VERSION 5.7 ;
  NOWIREEXTENSIONATPIN ON ;
  DIVIDERCHAR "/" ;
  BUSBITCHARS "[]" ;
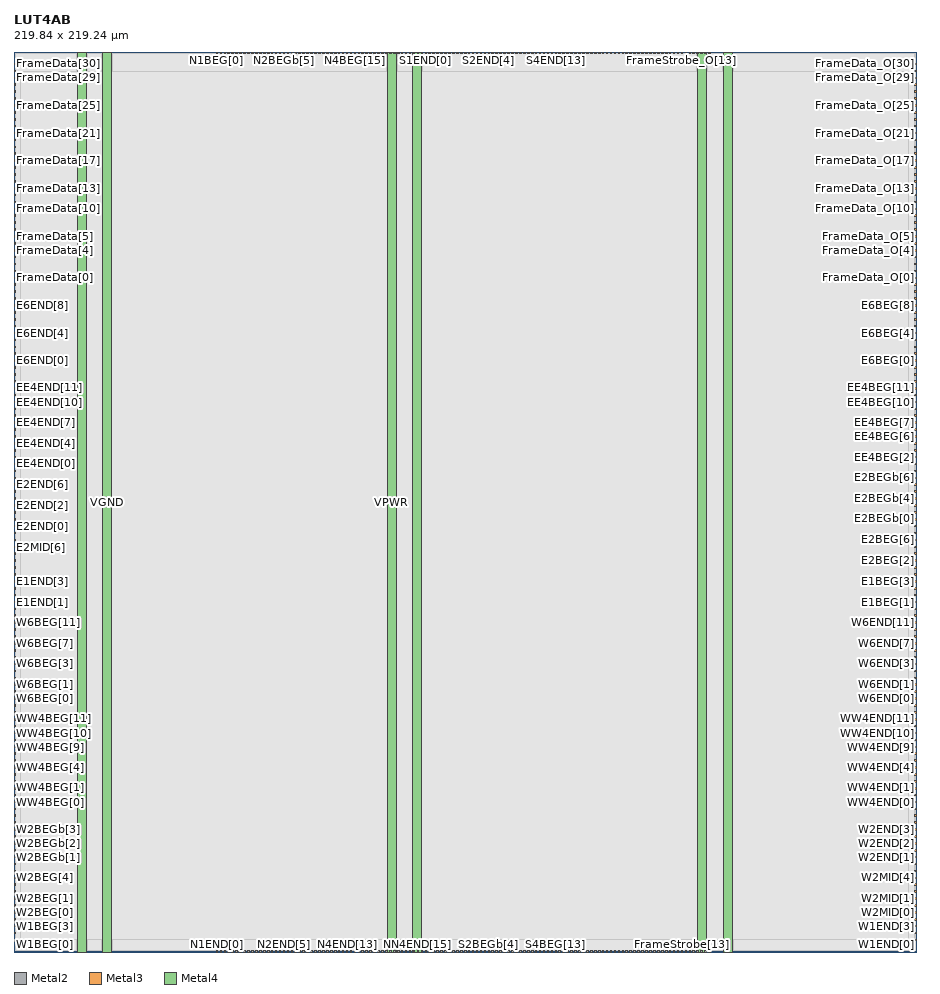
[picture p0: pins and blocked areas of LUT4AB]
MACRO LUT4AB
  CLASS BLOCK ;
  FOREIGN LUT4AB ;
  ORIGIN 0.000 0.000 ;
  SIZE 219.840 BY 219.240 ;
  PIN Ci
    DIRECTION INPUT ;
    USE SIGNAL ;
    ANTENNAGATEAREA 0.587600 ;
    PORT
      LAYER Metal2 ;
        RECT 99.160 0.000 99.560 0.400 ;
    END
  END Ci
  PIN Co
    DIRECTION OUTPUT ;
    USE SIGNAL ;
    ANTENNADIFFAREA 0.677200 ;
    PORT
      LAYER Metal2 ;
        RECT 99.160 218.840 99.560 219.240 ;
    END
  END Co
  PIN E1BEG[0]
    DIRECTION OUTPUT ;
    USE SIGNAL ;
    ANTENNADIFFAREA 0.708600 ;
    PORT
      LAYER Metal3 ;
        RECT 219.440 83.380 219.840 83.780 ;
    END
  END E1BEG[0]
  PIN E1BEG[1]
    DIRECTION OUTPUT ;
    USE SIGNAL ;
    ANTENNADIFFAREA 0.708600 ;
    PORT
      LAYER Metal3 ;
        RECT 219.440 85.060 219.840 85.460 ;
    END
  END E1BEG[1]
  PIN E1BEG[2]
    DIRECTION OUTPUT ;
    USE SIGNAL ;
    ANTENNADIFFAREA 0.708600 ;
    PORT
      LAYER Metal3 ;
        RECT 219.440 86.740 219.840 87.140 ;
    END
  END E1BEG[2]
  PIN E1BEG[3]
    DIRECTION OUTPUT ;
    USE SIGNAL ;
    ANTENNADIFFAREA 0.708600 ;
    PORT
      LAYER Metal3 ;
        RECT 219.440 88.420 219.840 88.820 ;
    END
  END E1BEG[3]
  PIN E1END[0]
    DIRECTION INPUT ;
    USE SIGNAL ;
    ANTENNAGATEAREA 1.917500 ;
    PORT
      LAYER Metal3 ;
        RECT 0.000 83.380 0.400 83.780 ;
    END
  END E1END[0]
  PIN E1END[1]
    DIRECTION INPUT ;
    USE SIGNAL ;
    ANTENNAGATEAREA 1.847300 ;
    PORT
      LAYER Metal3 ;
        RECT 0.000 85.060 0.400 85.460 ;
    END
  END E1END[1]
  PIN E1END[2]
    DIRECTION INPUT ;
    USE SIGNAL ;
    ANTENNAGATEAREA 2.448700 ;
    PORT
      LAYER Metal3 ;
        RECT 0.000 86.740 0.400 87.140 ;
    END
  END E1END[2]
  PIN E1END[3]
    DIRECTION INPUT ;
    USE SIGNAL ;
    ANTENNAGATEAREA 2.433100 ;
    PORT
      LAYER Metal3 ;
        RECT 0.000 88.420 0.400 88.820 ;
    END
  END E1END[3]
  PIN E2BEG[0]
    DIRECTION OUTPUT ;
    USE SIGNAL ;
    ANTENNADIFFAREA 0.708600 ;
    PORT
      LAYER Metal3 ;
        RECT 219.440 90.100 219.840 90.500 ;
    END
  END E2BEG[0]
  PIN E2BEG[1]
    DIRECTION OUTPUT ;
    USE SIGNAL ;
    ANTENNADIFFAREA 0.708600 ;
    PORT
      LAYER Metal3 ;
        RECT 219.440 91.780 219.840 92.180 ;
    END
  END E2BEG[1]
  PIN E2BEG[2]
    DIRECTION OUTPUT ;
    USE SIGNAL ;
    ANTENNADIFFAREA 0.708600 ;
    PORT
      LAYER Metal3 ;
        RECT 219.440 93.460 219.840 93.860 ;
    END
  END E2BEG[2]
  PIN E2BEG[3]
    DIRECTION OUTPUT ;
    USE SIGNAL ;
    ANTENNADIFFAREA 0.708600 ;
    PORT
      LAYER Metal3 ;
        RECT 219.440 95.140 219.840 95.540 ;
    END
  END E2BEG[3]
  PIN E2BEG[4]
    DIRECTION OUTPUT ;
    USE SIGNAL ;
    ANTENNADIFFAREA 0.708600 ;
    PORT
      LAYER Metal3 ;
        RECT 219.440 96.820 219.840 97.220 ;
    END
  END E2BEG[4]
  PIN E2BEG[5]
    DIRECTION OUTPUT ;
    USE SIGNAL ;
    ANTENNADIFFAREA 0.708600 ;
    PORT
      LAYER Metal3 ;
        RECT 219.440 98.500 219.840 98.900 ;
    END
  END E2BEG[5]
  PIN E2BEG[6]
    DIRECTION OUTPUT ;
    USE SIGNAL ;
    ANTENNADIFFAREA 0.708600 ;
    PORT
      LAYER Metal3 ;
        RECT 219.440 100.180 219.840 100.580 ;
    END
  END E2BEG[6]
  PIN E2BEG[7]
    DIRECTION OUTPUT ;
    USE SIGNAL ;
    ANTENNADIFFAREA 0.708600 ;
    PORT
      LAYER Metal3 ;
        RECT 219.440 101.860 219.840 102.260 ;
    END
  END E2BEG[7]
  PIN E2BEGb[0]
    DIRECTION OUTPUT ;
    USE SIGNAL ;
    ANTENNADIFFAREA 0.708600 ;
    PORT
      LAYER Metal3 ;
        RECT 219.440 103.540 219.840 103.940 ;
    END
  END E2BEGb[0]
  PIN E2BEGb[1]
    DIRECTION OUTPUT ;
    USE SIGNAL ;
    ANTENNADIFFAREA 0.708600 ;
    PORT
      LAYER Metal3 ;
        RECT 219.440 105.220 219.840 105.620 ;
    END
  END E2BEGb[1]
  PIN E2BEGb[2]
    DIRECTION OUTPUT ;
    USE SIGNAL ;
    ANTENNADIFFAREA 0.708600 ;
    PORT
      LAYER Metal3 ;
        RECT 219.440 106.900 219.840 107.300 ;
    END
  END E2BEGb[2]
  PIN E2BEGb[3]
    DIRECTION OUTPUT ;
    USE SIGNAL ;
    ANTENNADIFFAREA 0.708600 ;
    PORT
      LAYER Metal3 ;
        RECT 219.440 108.580 219.840 108.980 ;
    END
  END E2BEGb[3]
  PIN E2BEGb[4]
    DIRECTION OUTPUT ;
    USE SIGNAL ;
    ANTENNADIFFAREA 0.708600 ;
    PORT
      LAYER Metal3 ;
        RECT 219.440 110.260 219.840 110.660 ;
    END
  END E2BEGb[4]
  PIN E2BEGb[5]
    DIRECTION OUTPUT ;
    USE SIGNAL ;
    ANTENNADIFFAREA 0.708600 ;
    PORT
      LAYER Metal3 ;
        RECT 219.440 111.940 219.840 112.340 ;
    END
  END E2BEGb[5]
  PIN E2BEGb[6]
    DIRECTION OUTPUT ;
    USE SIGNAL ;
    ANTENNADIFFAREA 0.708600 ;
    PORT
      LAYER Metal3 ;
        RECT 219.440 113.620 219.840 114.020 ;
    END
  END E2BEGb[6]
  PIN E2BEGb[7]
    DIRECTION OUTPUT ;
    USE SIGNAL ;
    ANTENNADIFFAREA 0.708600 ;
    PORT
      LAYER Metal3 ;
        RECT 219.440 115.300 219.840 115.700 ;
    END
  END E2BEGb[7]
  PIN E2END[0]
    DIRECTION INPUT ;
    USE SIGNAL ;
    ANTENNAGATEAREA 0.944600 ;
    PORT
      LAYER Metal3 ;
        RECT 0.000 103.540 0.400 103.940 ;
    END
  END E2END[0]
  PIN E2END[1]
    DIRECTION INPUT ;
    USE SIGNAL ;
    ANTENNAGATEAREA 0.899100 ;
    PORT
      LAYER Metal3 ;
        RECT 0.000 105.220 0.400 105.620 ;
    END
  END E2END[1]
  PIN E2END[2]
    DIRECTION INPUT ;
    USE SIGNAL ;
    ANTENNAGATEAREA 1.498900 ;
    PORT
      LAYER Metal3 ;
        RECT 0.000 106.900 0.400 107.300 ;
    END
  END E2END[2]
  PIN E2END[3]
    DIRECTION INPUT ;
    USE SIGNAL ;
    ANTENNAGATEAREA 1.530100 ;
    PORT
      LAYER Metal3 ;
        RECT 0.000 108.580 0.400 108.980 ;
    END
  END E2END[3]
  PIN E2END[4]
    DIRECTION INPUT ;
    USE SIGNAL ;
    ANTENNAGATEAREA 1.059500 ;
    PORT
      LAYER Metal3 ;
        RECT 0.000 110.260 0.400 110.660 ;
    END
  END E2END[4]
  PIN E2END[5]
    DIRECTION INPUT ;
    USE SIGNAL ;
    ANTENNAGATEAREA 1.288300 ;
    PORT
      LAYER Metal3 ;
        RECT 0.000 111.940 0.400 112.340 ;
    END
  END E2END[5]
  PIN E2END[6]
    DIRECTION INPUT ;
    USE SIGNAL ;
    ANTENNAGATEAREA 1.439400 ;
    PORT
      LAYER Metal3 ;
        RECT 0.000 113.620 0.400 114.020 ;
    END
  END E2END[6]
  PIN E2END[7]
    DIRECTION INPUT ;
    USE SIGNAL ;
    ANTENNAGATEAREA 1.041300 ;
    PORT
      LAYER Metal3 ;
        RECT 0.000 115.300 0.400 115.700 ;
    END
  END E2END[7]
  PIN E2MID[0]
    DIRECTION INPUT ;
    USE SIGNAL ;
    ANTENNAGATEAREA 0.820300 ;
    ANTENNADIFFAREA 32.246399 ;
    PORT
      LAYER Metal3 ;
        RECT 0.000 90.100 0.400 90.500 ;
    END
  END E2MID[0]
  PIN E2MID[1]
    DIRECTION INPUT ;
    USE SIGNAL ;
    ANTENNAGATEAREA 1.033500 ;
    ANTENNADIFFAREA 10.077000 ;
    PORT
      LAYER Metal3 ;
        RECT 0.000 91.780 0.400 92.180 ;
    END
  END E2MID[1]
  PIN E2MID[2]
    DIRECTION INPUT ;
    USE SIGNAL ;
    ANTENNAGATEAREA 0.848900 ;
    ANTENNADIFFAREA 24.184799 ;
    PORT
      LAYER Metal3 ;
        RECT 0.000 93.460 0.400 93.860 ;
    END
  END E2MID[2]
  PIN E2MID[3]
    DIRECTION INPUT ;
    USE SIGNAL ;
    ANTENNAGATEAREA 1.033500 ;
    ANTENNADIFFAREA 50.384998 ;
    PORT
      LAYER Metal3 ;
        RECT 0.000 95.140 0.400 95.540 ;
    END
  END E2MID[3]
  PIN E2MID[4]
    DIRECTION INPUT ;
    USE SIGNAL ;
    ANTENNAGATEAREA 0.820300 ;
    ANTENNADIFFAREA 32.246399 ;
    PORT
      LAYER Metal3 ;
        RECT 0.000 96.820 0.400 97.220 ;
    END
  END E2MID[4]
  PIN E2MID[5]
    DIRECTION INPUT ;
    USE SIGNAL ;
    ANTENNAGATEAREA 1.033500 ;
    PORT
      LAYER Metal3 ;
        RECT 0.000 98.500 0.400 98.900 ;
    END
  END E2MID[5]
  PIN E2MID[6]
    DIRECTION INPUT ;
    USE SIGNAL ;
    ANTENNAGATEAREA 0.820300 ;
    PORT
      LAYER Metal3 ;
        RECT 0.000 100.180 0.400 100.580 ;
    END
  END E2MID[6]
  PIN E2MID[7]
    DIRECTION INPUT ;
    USE SIGNAL ;
    ANTENNAGATEAREA 1.033500 ;
    PORT
      LAYER Metal3 ;
        RECT 0.000 101.860 0.400 102.260 ;
    END
  END E2MID[7]
  PIN E6BEG[0]
    DIRECTION OUTPUT ;
    USE SIGNAL ;
    ANTENNADIFFAREA 0.708600 ;
    PORT
      LAYER Metal3 ;
        RECT 219.440 143.860 219.840 144.260 ;
    END
  END E6BEG[0]
  PIN E6BEG[10]
    DIRECTION OUTPUT ;
    USE SIGNAL ;
    ANTENNADIFFAREA 0.708600 ;
    PORT
      LAYER Metal3 ;
        RECT 219.440 160.660 219.840 161.060 ;
    END
  END E6BEG[10]
  PIN E6BEG[11]
    DIRECTION OUTPUT ;
    USE SIGNAL ;
    ANTENNADIFFAREA 0.708600 ;
    PORT
      LAYER Metal3 ;
        RECT 219.440 162.340 219.840 162.740 ;
    END
  END E6BEG[11]
  PIN E6BEG[1]
    DIRECTION OUTPUT ;
    USE SIGNAL ;
    ANTENNADIFFAREA 0.708600 ;
    PORT
      LAYER Metal3 ;
        RECT 219.440 145.540 219.840 145.940 ;
    END
  END E6BEG[1]
  PIN E6BEG[2]
    DIRECTION OUTPUT ;
    USE SIGNAL ;
    ANTENNADIFFAREA 0.708600 ;
    PORT
      LAYER Metal3 ;
        RECT 219.440 147.220 219.840 147.620 ;
    END
  END E6BEG[2]
  PIN E6BEG[3]
    DIRECTION OUTPUT ;
    USE SIGNAL ;
    ANTENNADIFFAREA 0.708600 ;
    PORT
      LAYER Metal3 ;
        RECT 219.440 148.900 219.840 149.300 ;
    END
  END E6BEG[3]
  PIN E6BEG[4]
    DIRECTION OUTPUT ;
    USE SIGNAL ;
    ANTENNADIFFAREA 0.708600 ;
    PORT
      LAYER Metal3 ;
        RECT 219.440 150.580 219.840 150.980 ;
    END
  END E6BEG[4]
  PIN E6BEG[5]
    DIRECTION OUTPUT ;
    USE SIGNAL ;
    ANTENNADIFFAREA 0.708600 ;
    PORT
      LAYER Metal3 ;
        RECT 219.440 152.260 219.840 152.660 ;
    END
  END E6BEG[5]
  PIN E6BEG[6]
    DIRECTION OUTPUT ;
    USE SIGNAL ;
    ANTENNADIFFAREA 0.708600 ;
    PORT
      LAYER Metal3 ;
        RECT 219.440 153.940 219.840 154.340 ;
    END
  END E6BEG[6]
  PIN E6BEG[7]
    DIRECTION OUTPUT ;
    USE SIGNAL ;
    ANTENNADIFFAREA 0.708600 ;
    PORT
      LAYER Metal3 ;
        RECT 219.440 155.620 219.840 156.020 ;
    END
  END E6BEG[7]
  PIN E6BEG[8]
    DIRECTION OUTPUT ;
    USE SIGNAL ;
    ANTENNADIFFAREA 0.708600 ;
    PORT
      LAYER Metal3 ;
        RECT 219.440 157.300 219.840 157.700 ;
    END
  END E6BEG[8]
  PIN E6BEG[9]
    DIRECTION OUTPUT ;
    USE SIGNAL ;
    ANTENNADIFFAREA 0.708600 ;
    PORT
      LAYER Metal3 ;
        RECT 219.440 158.980 219.840 159.380 ;
    END
  END E6BEG[9]
  PIN E6END[0]
    DIRECTION INPUT ;
    USE SIGNAL ;
    ANTENNAGATEAREA 2.678800 ;
    PORT
      LAYER Metal3 ;
        RECT 0.000 143.860 0.400 144.260 ;
    END
  END E6END[0]
  PIN E6END[10]
    DIRECTION INPUT ;
    USE SIGNAL ;
    ANTENNAGATEAREA 0.180700 ;
    PORT
      LAYER Metal3 ;
        RECT 0.000 160.660 0.400 161.060 ;
    END
  END E6END[10]
  PIN E6END[11]
    DIRECTION INPUT ;
    USE SIGNAL ;
    ANTENNAGATEAREA 0.180700 ;
    PORT
      LAYER Metal3 ;
        RECT 0.000 162.340 0.400 162.740 ;
    END
  END E6END[11]
  PIN E6END[1]
    DIRECTION INPUT ;
    USE SIGNAL ;
    ANTENNAGATEAREA 2.637700 ;
    PORT
      LAYER Metal3 ;
        RECT 0.000 145.540 0.400 145.940 ;
    END
  END E6END[1]
  PIN E6END[2]
    DIRECTION INPUT ;
    USE SIGNAL ;
    ANTENNAGATEAREA 0.180700 ;
    ANTENNADIFFAREA 2.015400 ;
    PORT
      LAYER Metal3 ;
        RECT 0.000 147.220 0.400 147.620 ;
    END
  END E6END[2]
  PIN E6END[3]
    DIRECTION INPUT ;
    USE SIGNAL ;
    ANTENNAGATEAREA 0.180700 ;
    ANTENNADIFFAREA 2.015400 ;
    PORT
      LAYER Metal3 ;
        RECT 0.000 148.900 0.400 149.300 ;
    END
  END E6END[3]
  PIN E6END[4]
    DIRECTION INPUT ;
    USE SIGNAL ;
    ANTENNAGATEAREA 0.180700 ;
    PORT
      LAYER Metal3 ;
        RECT 0.000 150.580 0.400 150.980 ;
    END
  END E6END[4]
  PIN E6END[5]
    DIRECTION INPUT ;
    USE SIGNAL ;
    ANTENNAGATEAREA 0.180700 ;
    ANTENNADIFFAREA 2.015400 ;
    PORT
      LAYER Metal3 ;
        RECT 0.000 152.260 0.400 152.660 ;
    END
  END E6END[5]
  PIN E6END[6]
    DIRECTION INPUT ;
    USE SIGNAL ;
    ANTENNAGATEAREA 0.180700 ;
    PORT
      LAYER Metal3 ;
        RECT 0.000 153.940 0.400 154.340 ;
    END
  END E6END[6]
  PIN E6END[7]
    DIRECTION INPUT ;
    USE SIGNAL ;
    ANTENNAGATEAREA 0.180700 ;
    PORT
      LAYER Metal3 ;
        RECT 0.000 155.620 0.400 156.020 ;
    END
  END E6END[7]
  PIN E6END[8]
    DIRECTION INPUT ;
    USE SIGNAL ;
    ANTENNAGATEAREA 0.180700 ;
    PORT
      LAYER Metal3 ;
        RECT 0.000 157.300 0.400 157.700 ;
    END
  END E6END[8]
  PIN E6END[9]
    DIRECTION INPUT ;
    USE SIGNAL ;
    ANTENNAGATEAREA 0.180700 ;
    PORT
      LAYER Metal3 ;
        RECT 0.000 158.980 0.400 159.380 ;
    END
  END E6END[9]
  PIN EE4BEG[0]
    DIRECTION OUTPUT ;
    USE SIGNAL ;
    ANTENNADIFFAREA 0.708600 ;
    PORT
      LAYER Metal3 ;
        RECT 219.440 116.980 219.840 117.380 ;
    END
  END EE4BEG[0]
  PIN EE4BEG[10]
    DIRECTION OUTPUT ;
    USE SIGNAL ;
    ANTENNADIFFAREA 0.708600 ;
    PORT
      LAYER Metal3 ;
        RECT 219.440 133.780 219.840 134.180 ;
    END
  END EE4BEG[10]
  PIN EE4BEG[11]
    DIRECTION OUTPUT ;
    USE SIGNAL ;
    ANTENNADIFFAREA 0.708600 ;
    PORT
      LAYER Metal3 ;
        RECT 219.440 135.460 219.840 135.860 ;
    END
  END EE4BEG[11]
  PIN EE4BEG[12]
    DIRECTION OUTPUT ;
    USE SIGNAL ;
    ANTENNADIFFAREA 0.708600 ;
    PORT
      LAYER Metal3 ;
        RECT 219.440 137.140 219.840 137.540 ;
    END
  END EE4BEG[12]
  PIN EE4BEG[13]
    DIRECTION OUTPUT ;
    USE SIGNAL ;
    ANTENNADIFFAREA 0.708600 ;
    PORT
      LAYER Metal3 ;
        RECT 219.440 138.820 219.840 139.220 ;
    END
  END EE4BEG[13]
  PIN EE4BEG[14]
    DIRECTION OUTPUT ;
    USE SIGNAL ;
    ANTENNADIFFAREA 0.708600 ;
    PORT
      LAYER Metal3 ;
        RECT 219.440 140.500 219.840 140.900 ;
    END
  END EE4BEG[14]
  PIN EE4BEG[15]
    DIRECTION OUTPUT ;
    USE SIGNAL ;
    ANTENNADIFFAREA 0.708600 ;
    PORT
      LAYER Metal3 ;
        RECT 219.440 142.180 219.840 142.580 ;
    END
  END EE4BEG[15]
  PIN EE4BEG[1]
    DIRECTION OUTPUT ;
    USE SIGNAL ;
    ANTENNADIFFAREA 0.708600 ;
    PORT
      LAYER Metal3 ;
        RECT 219.440 118.660 219.840 119.060 ;
    END
  END EE4BEG[1]
  PIN EE4BEG[2]
    DIRECTION OUTPUT ;
    USE SIGNAL ;
    ANTENNADIFFAREA 0.708600 ;
    PORT
      LAYER Metal3 ;
        RECT 219.440 120.340 219.840 120.740 ;
    END
  END EE4BEG[2]
  PIN EE4BEG[3]
    DIRECTION OUTPUT ;
    USE SIGNAL ;
    ANTENNADIFFAREA 0.708600 ;
    PORT
      LAYER Metal3 ;
        RECT 219.440 122.020 219.840 122.420 ;
    END
  END EE4BEG[3]
  PIN EE4BEG[4]
    DIRECTION OUTPUT ;
    USE SIGNAL ;
    ANTENNADIFFAREA 0.708600 ;
    PORT
      LAYER Metal3 ;
        RECT 219.440 123.700 219.840 124.100 ;
    END
  END EE4BEG[4]
  PIN EE4BEG[5]
    DIRECTION OUTPUT ;
    USE SIGNAL ;
    ANTENNADIFFAREA 0.708600 ;
    PORT
      LAYER Metal3 ;
        RECT 219.440 125.380 219.840 125.780 ;
    END
  END EE4BEG[5]
  PIN EE4BEG[6]
    DIRECTION OUTPUT ;
    USE SIGNAL ;
    ANTENNADIFFAREA 0.708600 ;
    PORT
      LAYER Metal3 ;
        RECT 219.440 127.060 219.840 127.460 ;
    END
  END EE4BEG[6]
  PIN EE4BEG[7]
    DIRECTION OUTPUT ;
    USE SIGNAL ;
    ANTENNADIFFAREA 0.708600 ;
    PORT
      LAYER Metal3 ;
        RECT 219.440 128.740 219.840 129.140 ;
    END
  END EE4BEG[7]
  PIN EE4BEG[8]
    DIRECTION OUTPUT ;
    USE SIGNAL ;
    ANTENNADIFFAREA 0.708600 ;
    PORT
      LAYER Metal3 ;
        RECT 219.440 130.420 219.840 130.820 ;
    END
  END EE4BEG[8]
  PIN EE4BEG[9]
    DIRECTION OUTPUT ;
    USE SIGNAL ;
    ANTENNADIFFAREA 0.708600 ;
    PORT
      LAYER Metal3 ;
        RECT 219.440 132.100 219.840 132.500 ;
    END
  END EE4BEG[9]
  PIN EE4END[0]
    DIRECTION INPUT ;
    USE SIGNAL ;
    ANTENNAGATEAREA 0.607100 ;
    PORT
      LAYER Metal3 ;
        RECT 0.000 116.980 0.400 117.380 ;
    END
  END EE4END[0]
  PIN EE4END[10]
    DIRECTION INPUT ;
    USE SIGNAL ;
    ANTENNAGATEAREA 0.180700 ;
    ANTENNADIFFAREA 2.015400 ;
    PORT
      LAYER Metal3 ;
        RECT 0.000 133.780 0.400 134.180 ;
    END
  END EE4END[10]
  PIN EE4END[11]
    DIRECTION INPUT ;
    USE SIGNAL ;
    ANTENNAGATEAREA 0.180700 ;
    ANTENNADIFFAREA 2.015400 ;
    PORT
      LAYER Metal3 ;
        RECT 0.000 135.460 0.400 135.860 ;
    END
  END EE4END[11]
  PIN EE4END[12]
    DIRECTION INPUT ;
    USE SIGNAL ;
    ANTENNAGATEAREA 0.180700 ;
    ANTENNADIFFAREA 2.015400 ;
    PORT
      LAYER Metal3 ;
        RECT 0.000 137.140 0.400 137.540 ;
    END
  END EE4END[12]
  PIN EE4END[13]
    DIRECTION INPUT ;
    USE SIGNAL ;
    ANTENNAGATEAREA 0.180700 ;
    ANTENNADIFFAREA 2.015400 ;
    PORT
      LAYER Metal3 ;
        RECT 0.000 138.820 0.400 139.220 ;
    END
  END EE4END[13]
  PIN EE4END[14]
    DIRECTION INPUT ;
    USE SIGNAL ;
    ANTENNAGATEAREA 0.180700 ;
    ANTENNADIFFAREA 2.015400 ;
    PORT
      LAYER Metal3 ;
        RECT 0.000 140.500 0.400 140.900 ;
    END
  END EE4END[14]
  PIN EE4END[15]
    DIRECTION INPUT ;
    USE SIGNAL ;
    ANTENNAGATEAREA 0.180700 ;
    ANTENNADIFFAREA 2.015400 ;
    PORT
      LAYER Metal3 ;
        RECT 0.000 142.180 0.400 142.580 ;
    END
  END EE4END[15]
  PIN EE4END[1]
    DIRECTION INPUT ;
    USE SIGNAL ;
    ANTENNAGATEAREA 0.620100 ;
    PORT
      LAYER Metal3 ;
        RECT 0.000 118.660 0.400 119.060 ;
    END
  END EE4END[1]
  PIN EE4END[2]
    DIRECTION INPUT ;
    USE SIGNAL ;
    ANTENNAGATEAREA 0.681200 ;
    PORT
      LAYER Metal3 ;
        RECT 0.000 120.340 0.400 120.740 ;
    END
  END EE4END[2]
  PIN EE4END[3]
    DIRECTION INPUT ;
    USE SIGNAL ;
    ANTENNAGATEAREA 0.678600 ;
    PORT
      LAYER Metal3 ;
        RECT 0.000 122.020 0.400 122.420 ;
    END
  END EE4END[3]
  PIN EE4END[4]
    DIRECTION INPUT ;
    USE SIGNAL ;
    ANTENNAGATEAREA 0.180700 ;
    ANTENNADIFFAREA 2.015400 ;
    PORT
      LAYER Metal3 ;
        RECT 0.000 123.700 0.400 124.100 ;
    END
  END EE4END[4]
  PIN EE4END[5]
    DIRECTION INPUT ;
    USE SIGNAL ;
    ANTENNAGATEAREA 0.180700 ;
    PORT
      LAYER Metal3 ;
        RECT 0.000 125.380 0.400 125.780 ;
    END
  END EE4END[5]
  PIN EE4END[6]
    DIRECTION INPUT ;
    USE SIGNAL ;
    ANTENNAGATEAREA 0.180700 ;
    PORT
      LAYER Metal3 ;
        RECT 0.000 127.060 0.400 127.460 ;
    END
  END EE4END[6]
  PIN EE4END[7]
    DIRECTION INPUT ;
    USE SIGNAL ;
    ANTENNAGATEAREA 0.180700 ;
    ANTENNADIFFAREA 2.015400 ;
    PORT
      LAYER Metal3 ;
        RECT 0.000 128.740 0.400 129.140 ;
    END
  END EE4END[7]
  PIN EE4END[8]
    DIRECTION INPUT ;
    USE SIGNAL ;
    ANTENNAGATEAREA 0.180700 ;
    ANTENNADIFFAREA 2.015400 ;
    PORT
      LAYER Metal3 ;
        RECT 0.000 130.420 0.400 130.820 ;
    END
  END EE4END[8]
  PIN EE4END[9]
    DIRECTION INPUT ;
    USE SIGNAL ;
    ANTENNAGATEAREA 0.180700 ;
    ANTENNADIFFAREA 2.015400 ;
    PORT
      LAYER Metal3 ;
        RECT 0.000 132.100 0.400 132.500 ;
    END
  END EE4END[9]
  PIN FrameData[0]
    DIRECTION INPUT ;
    USE SIGNAL ;
    ANTENNAGATEAREA 3.071900 ;
    PORT
      LAYER Metal3 ;
        RECT 0.000 164.020 0.400 164.420 ;
    END
  END FrameData[0]
  PIN FrameData[10]
    DIRECTION INPUT ;
    USE SIGNAL ;
    ANTENNAGATEAREA 3.794700 ;
    PORT
      LAYER Metal3 ;
        RECT 0.000 180.820 0.400 181.220 ;
    END
  END FrameData[10]
  PIN FrameData[11]
    DIRECTION INPUT ;
    USE SIGNAL ;
    ANTENNAGATEAREA 3.794700 ;
    PORT
      LAYER Metal3 ;
        RECT 0.000 182.500 0.400 182.900 ;
    END
  END FrameData[11]
  PIN FrameData[12]
    DIRECTION INPUT ;
    USE SIGNAL ;
    ANTENNAGATEAREA 3.794700 ;
    PORT
      LAYER Metal3 ;
        RECT 0.000 184.180 0.400 184.580 ;
    END
  END FrameData[12]
  PIN FrameData[13]
    DIRECTION INPUT ;
    USE SIGNAL ;
    ANTENNAGATEAREA 3.794700 ;
    PORT
      LAYER Metal3 ;
        RECT 0.000 185.860 0.400 186.260 ;
    END
  END FrameData[13]
  PIN FrameData[14]
    DIRECTION INPUT ;
    USE SIGNAL ;
    ANTENNAGATEAREA 3.794700 ;
    PORT
      LAYER Metal3 ;
        RECT 0.000 187.540 0.400 187.940 ;
    END
  END FrameData[14]
  PIN FrameData[15]
    DIRECTION INPUT ;
    USE SIGNAL ;
    ANTENNAGATEAREA 3.794700 ;
    PORT
      LAYER Metal3 ;
        RECT 0.000 189.220 0.400 189.620 ;
    END
  END FrameData[15]
  PIN FrameData[16]
    DIRECTION INPUT ;
    USE SIGNAL ;
    ANTENNAGATEAREA 3.794700 ;
    PORT
      LAYER Metal3 ;
        RECT 0.000 190.900 0.400 191.300 ;
    END
  END FrameData[16]
  PIN FrameData[17]
    DIRECTION INPUT ;
    USE SIGNAL ;
    ANTENNAGATEAREA 3.794700 ;
    PORT
      LAYER Metal3 ;
        RECT 0.000 192.580 0.400 192.980 ;
    END
  END FrameData[17]
  PIN FrameData[18]
    DIRECTION INPUT ;
    USE SIGNAL ;
    ANTENNAGATEAREA 3.794700 ;
    PORT
      LAYER Metal3 ;
        RECT 0.000 194.260 0.400 194.660 ;
    END
  END FrameData[18]
  PIN FrameData[19]
    DIRECTION INPUT ;
    USE SIGNAL ;
    ANTENNAGATEAREA 3.794700 ;
    PORT
      LAYER Metal3 ;
        RECT 0.000 195.940 0.400 196.340 ;
    END
  END FrameData[19]
  PIN FrameData[1]
    DIRECTION INPUT ;
    USE SIGNAL ;
    ANTENNAGATEAREA 3.433300 ;
    PORT
      LAYER Metal3 ;
        RECT 0.000 165.700 0.400 166.100 ;
    END
  END FrameData[1]
  PIN FrameData[20]
    DIRECTION INPUT ;
    USE SIGNAL ;
    ANTENNAGATEAREA 3.794700 ;
    PORT
      LAYER Metal3 ;
        RECT 0.000 197.620 0.400 198.020 ;
    END
  END FrameData[20]
  PIN FrameData[21]
    DIRECTION INPUT ;
    USE SIGNAL ;
    ANTENNAGATEAREA 3.794700 ;
    PORT
      LAYER Metal3 ;
        RECT 0.000 199.300 0.400 199.700 ;
    END
  END FrameData[21]
  PIN FrameData[22]
    DIRECTION INPUT ;
    USE SIGNAL ;
    ANTENNAGATEAREA 3.794700 ;
    PORT
      LAYER Metal3 ;
        RECT 0.000 200.980 0.400 201.380 ;
    END
  END FrameData[22]
  PIN FrameData[23]
    DIRECTION INPUT ;
    USE SIGNAL ;
    ANTENNAGATEAREA 3.794700 ;
    PORT
      LAYER Metal3 ;
        RECT 0.000 202.660 0.400 203.060 ;
    END
  END FrameData[23]
  PIN FrameData[24]
    DIRECTION INPUT ;
    USE SIGNAL ;
    ANTENNAGATEAREA 3.794700 ;
    PORT
      LAYER Metal3 ;
        RECT 0.000 204.340 0.400 204.740 ;
    END
  END FrameData[24]
  PIN FrameData[25]
    DIRECTION INPUT ;
    USE SIGNAL ;
    ANTENNAGATEAREA 3.614000 ;
    PORT
      LAYER Metal3 ;
        RECT 0.000 206.020 0.400 206.420 ;
    END
  END FrameData[25]
  PIN FrameData[26]
    DIRECTION INPUT ;
    USE SIGNAL ;
    ANTENNAGATEAREA 3.433300 ;
    PORT
      LAYER Metal3 ;
        RECT 0.000 207.700 0.400 208.100 ;
    END
  END FrameData[26]
  PIN FrameData[27]
    DIRECTION INPUT ;
    USE SIGNAL ;
    ANTENNAGATEAREA 3.433300 ;
    PORT
      LAYER Metal3 ;
        RECT 0.000 209.380 0.400 209.780 ;
    END
  END FrameData[27]
  PIN FrameData[28]
    DIRECTION INPUT ;
    USE SIGNAL ;
    ANTENNAGATEAREA 3.433300 ;
    PORT
      LAYER Metal3 ;
        RECT 0.000 211.060 0.400 211.460 ;
    END
  END FrameData[28]
  PIN FrameData[29]
    DIRECTION INPUT ;
    USE SIGNAL ;
    ANTENNAGATEAREA 3.252600 ;
    PORT
      LAYER Metal3 ;
        RECT 0.000 212.740 0.400 213.140 ;
    END
  END FrameData[29]
  PIN FrameData[2]
    DIRECTION INPUT ;
    USE SIGNAL ;
    ANTENNAGATEAREA 3.433300 ;
    PORT
      LAYER Metal3 ;
        RECT 0.000 167.380 0.400 167.780 ;
    END
  END FrameData[2]
  PIN FrameData[30]
    DIRECTION INPUT ;
    USE SIGNAL ;
    ANTENNAGATEAREA 3.433300 ;
    PORT
      LAYER Metal3 ;
        RECT 0.000 214.420 0.400 214.820 ;
    END
  END FrameData[30]
  PIN FrameData[31]
    DIRECTION INPUT ;
    USE SIGNAL ;
    ANTENNAGATEAREA 3.433300 ;
    PORT
      LAYER Metal3 ;
        RECT 0.000 216.100 0.400 216.500 ;
    END
  END FrameData[31]
  PIN FrameData[3]
    DIRECTION INPUT ;
    USE SIGNAL ;
    ANTENNAGATEAREA 3.614000 ;
    PORT
      LAYER Metal3 ;
        RECT 0.000 169.060 0.400 169.460 ;
    END
  END FrameData[3]
  PIN FrameData[4]
    DIRECTION INPUT ;
    USE SIGNAL ;
    ANTENNAGATEAREA 3.794700 ;
    PORT
      LAYER Metal3 ;
        RECT 0.000 170.740 0.400 171.140 ;
    END
  END FrameData[4]
  PIN FrameData[5]
    DIRECTION INPUT ;
    USE SIGNAL ;
    ANTENNAGATEAREA 3.794700 ;
    PORT
      LAYER Metal3 ;
        RECT 0.000 172.420 0.400 172.820 ;
    END
  END FrameData[5]
  PIN FrameData[6]
    DIRECTION INPUT ;
    USE SIGNAL ;
    ANTENNAGATEAREA 3.614000 ;
    PORT
      LAYER Metal3 ;
        RECT 0.000 174.100 0.400 174.500 ;
    END
  END FrameData[6]
  PIN FrameData[7]
    DIRECTION INPUT ;
    USE SIGNAL ;
    ANTENNAGATEAREA 3.794700 ;
    PORT
      LAYER Metal3 ;
        RECT 0.000 175.780 0.400 176.180 ;
    END
  END FrameData[7]
  PIN FrameData[8]
    DIRECTION INPUT ;
    USE SIGNAL ;
    ANTENNAGATEAREA 3.794700 ;
    PORT
      LAYER Metal3 ;
        RECT 0.000 177.460 0.400 177.860 ;
    END
  END FrameData[8]
  PIN FrameData[9]
    DIRECTION INPUT ;
    USE SIGNAL ;
    ANTENNAGATEAREA 3.794700 ;
    PORT
      LAYER Metal3 ;
        RECT 0.000 179.140 0.400 179.540 ;
    END
  END FrameData[9]
  PIN FrameData_O[0]
    DIRECTION OUTPUT ;
    USE SIGNAL ;
    ANTENNADIFFAREA 0.708600 ;
    PORT
      LAYER Metal3 ;
        RECT 219.440 164.020 219.840 164.420 ;
    END
  END FrameData_O[0]
  PIN FrameData_O[10]
    DIRECTION OUTPUT ;
    USE SIGNAL ;
    ANTENNADIFFAREA 0.708600 ;
    PORT
      LAYER Metal3 ;
        RECT 219.440 180.820 219.840 181.220 ;
    END
  END FrameData_O[10]
  PIN FrameData_O[11]
    DIRECTION OUTPUT ;
    USE SIGNAL ;
    ANTENNADIFFAREA 0.708600 ;
    PORT
      LAYER Metal3 ;
        RECT 219.440 182.500 219.840 182.900 ;
    END
  END FrameData_O[11]
  PIN FrameData_O[12]
    DIRECTION OUTPUT ;
    USE SIGNAL ;
    ANTENNADIFFAREA 0.708600 ;
    PORT
      LAYER Metal3 ;
        RECT 219.440 184.180 219.840 184.580 ;
    END
  END FrameData_O[12]
  PIN FrameData_O[13]
    DIRECTION OUTPUT ;
    USE SIGNAL ;
    ANTENNADIFFAREA 0.708600 ;
    PORT
      LAYER Metal3 ;
        RECT 219.440 185.860 219.840 186.260 ;
    END
  END FrameData_O[13]
  PIN FrameData_O[14]
    DIRECTION OUTPUT ;
    USE SIGNAL ;
    ANTENNADIFFAREA 0.708600 ;
    PORT
      LAYER Metal3 ;
        RECT 219.440 187.540 219.840 187.940 ;
    END
  END FrameData_O[14]
  PIN FrameData_O[15]
    DIRECTION OUTPUT ;
    USE SIGNAL ;
    ANTENNADIFFAREA 0.708600 ;
    PORT
      LAYER Metal3 ;
        RECT 219.440 189.220 219.840 189.620 ;
    END
  END FrameData_O[15]
  PIN FrameData_O[16]
    DIRECTION OUTPUT ;
    USE SIGNAL ;
    ANTENNADIFFAREA 0.708600 ;
    PORT
      LAYER Metal3 ;
        RECT 219.440 190.900 219.840 191.300 ;
    END
  END FrameData_O[16]
  PIN FrameData_O[17]
    DIRECTION OUTPUT ;
    USE SIGNAL ;
    ANTENNADIFFAREA 0.708600 ;
    PORT
      LAYER Metal3 ;
        RECT 219.440 192.580 219.840 192.980 ;
    END
  END FrameData_O[17]
  PIN FrameData_O[18]
    DIRECTION OUTPUT ;
    USE SIGNAL ;
    ANTENNADIFFAREA 0.708600 ;
    PORT
      LAYER Metal3 ;
        RECT 219.440 194.260 219.840 194.660 ;
    END
  END FrameData_O[18]
  PIN FrameData_O[19]
    DIRECTION OUTPUT ;
    USE SIGNAL ;
    ANTENNADIFFAREA 0.708600 ;
    PORT
      LAYER Metal3 ;
        RECT 219.440 195.940 219.840 196.340 ;
    END
  END FrameData_O[19]
  PIN FrameData_O[1]
    DIRECTION OUTPUT ;
    USE SIGNAL ;
    ANTENNADIFFAREA 0.708600 ;
    PORT
      LAYER Metal3 ;
        RECT 219.440 165.700 219.840 166.100 ;
    END
  END FrameData_O[1]
  PIN FrameData_O[20]
    DIRECTION OUTPUT ;
    USE SIGNAL ;
    ANTENNADIFFAREA 0.708600 ;
    PORT
      LAYER Metal3 ;
        RECT 219.440 197.620 219.840 198.020 ;
    END
  END FrameData_O[20]
  PIN FrameData_O[21]
    DIRECTION OUTPUT ;
    USE SIGNAL ;
    ANTENNADIFFAREA 0.708600 ;
    PORT
      LAYER Metal3 ;
        RECT 219.440 199.300 219.840 199.700 ;
    END
  END FrameData_O[21]
  PIN FrameData_O[22]
    DIRECTION OUTPUT ;
    USE SIGNAL ;
    ANTENNADIFFAREA 0.708600 ;
    PORT
      LAYER Metal3 ;
        RECT 219.440 200.980 219.840 201.380 ;
    END
  END FrameData_O[22]
  PIN FrameData_O[23]
    DIRECTION OUTPUT ;
    USE SIGNAL ;
    ANTENNADIFFAREA 0.708600 ;
    PORT
      LAYER Metal3 ;
        RECT 219.440 202.660 219.840 203.060 ;
    END
  END FrameData_O[23]
  PIN FrameData_O[24]
    DIRECTION OUTPUT ;
    USE SIGNAL ;
    ANTENNADIFFAREA 0.708600 ;
    PORT
      LAYER Metal3 ;
        RECT 219.440 204.340 219.840 204.740 ;
    END
  END FrameData_O[24]
  PIN FrameData_O[25]
    DIRECTION OUTPUT ;
    USE SIGNAL ;
    ANTENNADIFFAREA 0.708600 ;
    PORT
      LAYER Metal3 ;
        RECT 219.440 206.020 219.840 206.420 ;
    END
  END FrameData_O[25]
  PIN FrameData_O[26]
    DIRECTION OUTPUT ;
    USE SIGNAL ;
    ANTENNADIFFAREA 0.708600 ;
    PORT
      LAYER Metal3 ;
        RECT 219.440 207.700 219.840 208.100 ;
    END
  END FrameData_O[26]
  PIN FrameData_O[27]
    DIRECTION OUTPUT ;
    USE SIGNAL ;
    ANTENNADIFFAREA 0.708600 ;
    PORT
      LAYER Metal3 ;
        RECT 219.440 209.380 219.840 209.780 ;
    END
  END FrameData_O[27]
  PIN FrameData_O[28]
    DIRECTION OUTPUT ;
    USE SIGNAL ;
    ANTENNADIFFAREA 0.708600 ;
    PORT
      LAYER Metal3 ;
        RECT 219.440 211.060 219.840 211.460 ;
    END
  END FrameData_O[28]
  PIN FrameData_O[29]
    DIRECTION OUTPUT ;
    USE SIGNAL ;
    ANTENNADIFFAREA 0.708600 ;
    PORT
      LAYER Metal3 ;
        RECT 219.440 212.740 219.840 213.140 ;
    END
  END FrameData_O[29]
  PIN FrameData_O[2]
    DIRECTION OUTPUT ;
    USE SIGNAL ;
    ANTENNADIFFAREA 0.708600 ;
    PORT
      LAYER Metal3 ;
        RECT 219.440 167.380 219.840 167.780 ;
    END
  END FrameData_O[2]
  PIN FrameData_O[30]
    DIRECTION OUTPUT ;
    USE SIGNAL ;
    ANTENNADIFFAREA 0.708600 ;
    PORT
      LAYER Metal3 ;
        RECT 219.440 214.420 219.840 214.820 ;
    END
  END FrameData_O[30]
  PIN FrameData_O[31]
    DIRECTION OUTPUT ;
    USE SIGNAL ;
    ANTENNADIFFAREA 0.708600 ;
    PORT
      LAYER Metal3 ;
        RECT 219.440 216.100 219.840 216.500 ;
    END
  END FrameData_O[31]
  PIN FrameData_O[3]
    DIRECTION OUTPUT ;
    USE SIGNAL ;
    ANTENNADIFFAREA 0.708600 ;
    PORT
      LAYER Metal3 ;
        RECT 219.440 169.060 219.840 169.460 ;
    END
  END FrameData_O[3]
  PIN FrameData_O[4]
    DIRECTION OUTPUT ;
    USE SIGNAL ;
    ANTENNADIFFAREA 0.708600 ;
    PORT
      LAYER Metal3 ;
        RECT 219.440 170.740 219.840 171.140 ;
    END
  END FrameData_O[4]
  PIN FrameData_O[5]
    DIRECTION OUTPUT ;
    USE SIGNAL ;
    ANTENNADIFFAREA 0.708600 ;
    PORT
      LAYER Metal3 ;
        RECT 219.440 172.420 219.840 172.820 ;
    END
  END FrameData_O[5]
  PIN FrameData_O[6]
    DIRECTION OUTPUT ;
    USE SIGNAL ;
    ANTENNADIFFAREA 0.708600 ;
    PORT
      LAYER Metal3 ;
        RECT 219.440 174.100 219.840 174.500 ;
    END
  END FrameData_O[6]
  PIN FrameData_O[7]
    DIRECTION OUTPUT ;
    USE SIGNAL ;
    ANTENNADIFFAREA 0.708600 ;
    PORT
      LAYER Metal3 ;
        RECT 219.440 175.780 219.840 176.180 ;
    END
  END FrameData_O[7]
  PIN FrameData_O[8]
    DIRECTION OUTPUT ;
    USE SIGNAL ;
    ANTENNADIFFAREA 0.708600 ;
    PORT
      LAYER Metal3 ;
        RECT 219.440 177.460 219.840 177.860 ;
    END
  END FrameData_O[8]
  PIN FrameData_O[9]
    DIRECTION OUTPUT ;
    USE SIGNAL ;
    ANTENNADIFFAREA 0.708600 ;
    PORT
      LAYER Metal3 ;
        RECT 219.440 179.140 219.840 179.540 ;
    END
  END FrameData_O[9]
  PIN FrameStrobe[0]
    DIRECTION INPUT ;
    USE SIGNAL ;
    ANTENNAGATEAREA 5.110300 ;
    PORT
      LAYER Metal2 ;
        RECT 150.040 0.000 150.440 0.400 ;
    END
  END FrameStrobe[0]
  PIN FrameStrobe[10]
    DIRECTION INPUT ;
    USE SIGNAL ;
    ANTENNAGATEAREA 6.753500 ;
    PORT
      LAYER Metal2 ;
        RECT 159.640 0.000 160.040 0.400 ;
    END
  END FrameStrobe[10]
  PIN FrameStrobe[11]
    DIRECTION INPUT ;
    USE SIGNAL ;
    ANTENNAGATEAREA 6.753500 ;
    PORT
      LAYER Metal2 ;
        RECT 160.600 0.000 161.000 0.400 ;
    END
  END FrameStrobe[11]
  PIN FrameStrobe[12]
    DIRECTION INPUT ;
    USE SIGNAL ;
    ANTENNAGATEAREA 6.753500 ;
    PORT
      LAYER Metal2 ;
        RECT 161.560 0.000 161.960 0.400 ;
    END
  END FrameStrobe[12]
  PIN FrameStrobe[13]
    DIRECTION INPUT ;
    USE SIGNAL ;
    ANTENNAGATEAREA 6.753500 ;
    PORT
      LAYER Metal2 ;
        RECT 162.520 0.000 162.920 0.400 ;
    END
  END FrameStrobe[13]
  PIN FrameStrobe[14]
    DIRECTION INPUT ;
    USE SIGNAL ;
    ANTENNAGATEAREA 6.753500 ;
    PORT
      LAYER Metal2 ;
        RECT 163.480 0.000 163.880 0.400 ;
    END
  END FrameStrobe[14]
  PIN FrameStrobe[15]
    DIRECTION INPUT ;
    USE SIGNAL ;
    ANTENNAGATEAREA 6.753500 ;
    PORT
      LAYER Metal2 ;
        RECT 164.440 0.000 164.840 0.400 ;
    END
  END FrameStrobe[15]
  PIN FrameStrobe[16]
    DIRECTION INPUT ;
    USE SIGNAL ;
    ANTENNAGATEAREA 6.753500 ;
    PORT
      LAYER Metal2 ;
        RECT 165.400 0.000 165.800 0.400 ;
    END
  END FrameStrobe[16]
  PIN FrameStrobe[17]
    DIRECTION INPUT ;
    USE SIGNAL ;
    ANTENNAGATEAREA 6.753500 ;
    PORT
      LAYER Metal2 ;
        RECT 166.360 0.000 166.760 0.400 ;
    END
  END FrameStrobe[17]
  PIN FrameStrobe[18]
    DIRECTION INPUT ;
    USE SIGNAL ;
    ANTENNAGATEAREA 6.753500 ;
    PORT
      LAYER Metal2 ;
        RECT 167.320 0.000 167.720 0.400 ;
    END
  END FrameStrobe[18]
  PIN FrameStrobe[19]
    DIRECTION INPUT ;
    USE SIGNAL ;
    ANTENNAGATEAREA 5.110300 ;
    PORT
      LAYER Metal2 ;
        RECT 168.280 0.000 168.680 0.400 ;
    END
  END FrameStrobe[19]
  PIN FrameStrobe[1]
    DIRECTION INPUT ;
    USE SIGNAL ;
    ANTENNAGATEAREA 6.137300 ;
    PORT
      LAYER Metal2 ;
        RECT 151.000 0.000 151.400 0.400 ;
    END
  END FrameStrobe[1]
  PIN FrameStrobe[2]
    DIRECTION INPUT ;
    USE SIGNAL ;
    ANTENNAGATEAREA 5.931900 ;
    PORT
      LAYER Metal2 ;
        RECT 151.960 0.000 152.360 0.400 ;
    END
  END FrameStrobe[2]
  PIN FrameStrobe[3]
    DIRECTION INPUT ;
    USE SIGNAL ;
    ANTENNAGATEAREA 6.548100 ;
    PORT
      LAYER Metal2 ;
        RECT 152.920 0.000 153.320 0.400 ;
    END
  END FrameStrobe[3]
  PIN FrameStrobe[4]
    DIRECTION INPUT ;
    USE SIGNAL ;
    ANTENNAGATEAREA 6.753500 ;
    PORT
      LAYER Metal2 ;
        RECT 153.880 0.000 154.280 0.400 ;
    END
  END FrameStrobe[4]
  PIN FrameStrobe[5]
    DIRECTION INPUT ;
    USE SIGNAL ;
    ANTENNAGATEAREA 6.753500 ;
    PORT
      LAYER Metal2 ;
        RECT 154.840 0.000 155.240 0.400 ;
    END
  END FrameStrobe[5]
  PIN FrameStrobe[6]
    DIRECTION INPUT ;
    USE SIGNAL ;
    ANTENNAGATEAREA 6.753500 ;
    PORT
      LAYER Metal2 ;
        RECT 155.800 0.000 156.200 0.400 ;
    END
  END FrameStrobe[6]
  PIN FrameStrobe[7]
    DIRECTION INPUT ;
    USE SIGNAL ;
    ANTENNAGATEAREA 6.753500 ;
    PORT
      LAYER Metal2 ;
        RECT 156.760 0.000 157.160 0.400 ;
    END
  END FrameStrobe[7]
  PIN FrameStrobe[8]
    DIRECTION INPUT ;
    USE SIGNAL ;
    ANTENNAGATEAREA 6.753500 ;
    PORT
      LAYER Metal2 ;
        RECT 157.720 0.000 158.120 0.400 ;
    END
  END FrameStrobe[8]
  PIN FrameStrobe[9]
    DIRECTION INPUT ;
    USE SIGNAL ;
    ANTENNAGATEAREA 6.753500 ;
    PORT
      LAYER Metal2 ;
        RECT 158.680 0.000 159.080 0.400 ;
    END
  END FrameStrobe[9]
  PIN FrameStrobe_O[0]
    DIRECTION OUTPUT ;
    USE SIGNAL ;
    ANTENNADIFFAREA 0.708600 ;
    PORT
      LAYER Metal2 ;
        RECT 150.040 218.840 150.440 219.240 ;
    END
  END FrameStrobe_O[0]
  PIN FrameStrobe_O[10]
    DIRECTION OUTPUT ;
    USE SIGNAL ;
    ANTENNADIFFAREA 0.708600 ;
    PORT
      LAYER Metal2 ;
        RECT 159.640 218.840 160.040 219.240 ;
    END
  END FrameStrobe_O[10]
  PIN FrameStrobe_O[11]
    DIRECTION OUTPUT ;
    USE SIGNAL ;
    ANTENNADIFFAREA 0.708600 ;
    PORT
      LAYER Metal2 ;
        RECT 160.600 218.840 161.000 219.240 ;
    END
  END FrameStrobe_O[11]
  PIN FrameStrobe_O[12]
    DIRECTION OUTPUT ;
    USE SIGNAL ;
    ANTENNADIFFAREA 0.708600 ;
    PORT
      LAYER Metal2 ;
        RECT 161.560 218.840 161.960 219.240 ;
    END
  END FrameStrobe_O[12]
  PIN FrameStrobe_O[13]
    DIRECTION OUTPUT ;
    USE SIGNAL ;
    ANTENNADIFFAREA 0.708600 ;
    PORT
      LAYER Metal2 ;
        RECT 162.520 218.840 162.920 219.240 ;
    END
  END FrameStrobe_O[13]
  PIN FrameStrobe_O[14]
    DIRECTION OUTPUT ;
    USE SIGNAL ;
    ANTENNADIFFAREA 0.708600 ;
    PORT
      LAYER Metal2 ;
        RECT 163.480 218.840 163.880 219.240 ;
    END
  END FrameStrobe_O[14]
  PIN FrameStrobe_O[15]
    DIRECTION OUTPUT ;
    USE SIGNAL ;
    ANTENNADIFFAREA 0.708600 ;
    PORT
      LAYER Metal2 ;
        RECT 164.440 218.840 164.840 219.240 ;
    END
  END FrameStrobe_O[15]
  PIN FrameStrobe_O[16]
    DIRECTION OUTPUT ;
    USE SIGNAL ;
    ANTENNADIFFAREA 0.708600 ;
    PORT
      LAYER Metal2 ;
        RECT 165.400 218.840 165.800 219.240 ;
    END
  END FrameStrobe_O[16]
  PIN FrameStrobe_O[17]
    DIRECTION OUTPUT ;
    USE SIGNAL ;
    ANTENNADIFFAREA 0.708600 ;
    PORT
      LAYER Metal2 ;
        RECT 166.360 218.840 166.760 219.240 ;
    END
  END FrameStrobe_O[17]
  PIN FrameStrobe_O[18]
    DIRECTION OUTPUT ;
    USE SIGNAL ;
    ANTENNADIFFAREA 0.708600 ;
    PORT
      LAYER Metal2 ;
        RECT 167.320 218.840 167.720 219.240 ;
    END
  END FrameStrobe_O[18]
  PIN FrameStrobe_O[19]
    DIRECTION OUTPUT ;
    USE SIGNAL ;
    ANTENNADIFFAREA 0.708600 ;
    PORT
      LAYER Metal2 ;
        RECT 168.280 218.840 168.680 219.240 ;
    END
  END FrameStrobe_O[19]
  PIN FrameStrobe_O[1]
    DIRECTION OUTPUT ;
    USE SIGNAL ;
    ANTENNADIFFAREA 0.708600 ;
    PORT
      LAYER Metal2 ;
        RECT 151.000 218.840 151.400 219.240 ;
    END
  END FrameStrobe_O[1]
  PIN FrameStrobe_O[2]
    DIRECTION OUTPUT ;
    USE SIGNAL ;
    ANTENNADIFFAREA 0.708600 ;
    PORT
      LAYER Metal2 ;
        RECT 151.960 218.840 152.360 219.240 ;
    END
  END FrameStrobe_O[2]
  PIN FrameStrobe_O[3]
    DIRECTION OUTPUT ;
    USE SIGNAL ;
    ANTENNADIFFAREA 0.708600 ;
    PORT
      LAYER Metal2 ;
        RECT 152.920 218.840 153.320 219.240 ;
    END
  END FrameStrobe_O[3]
  PIN FrameStrobe_O[4]
    DIRECTION OUTPUT ;
    USE SIGNAL ;
    ANTENNADIFFAREA 0.708600 ;
    PORT
      LAYER Metal2 ;
        RECT 153.880 218.840 154.280 219.240 ;
    END
  END FrameStrobe_O[4]
  PIN FrameStrobe_O[5]
    DIRECTION OUTPUT ;
    USE SIGNAL ;
    ANTENNADIFFAREA 0.708600 ;
    PORT
      LAYER Metal2 ;
        RECT 154.840 218.840 155.240 219.240 ;
    END
  END FrameStrobe_O[5]
  PIN FrameStrobe_O[6]
    DIRECTION OUTPUT ;
    USE SIGNAL ;
    ANTENNADIFFAREA 0.708600 ;
    PORT
      LAYER Metal2 ;
        RECT 155.800 218.840 156.200 219.240 ;
    END
  END FrameStrobe_O[6]
  PIN FrameStrobe_O[7]
    DIRECTION OUTPUT ;
    USE SIGNAL ;
    ANTENNADIFFAREA 0.708600 ;
    PORT
      LAYER Metal2 ;
        RECT 156.760 218.840 157.160 219.240 ;
    END
  END FrameStrobe_O[7]
  PIN FrameStrobe_O[8]
    DIRECTION OUTPUT ;
    USE SIGNAL ;
    ANTENNADIFFAREA 0.708600 ;
    PORT
      LAYER Metal2 ;
        RECT 157.720 218.840 158.120 219.240 ;
    END
  END FrameStrobe_O[8]
  PIN FrameStrobe_O[9]
    DIRECTION OUTPUT ;
    USE SIGNAL ;
    ANTENNADIFFAREA 0.708600 ;
    PORT
      LAYER Metal2 ;
        RECT 158.680 218.840 159.080 219.240 ;
    END
  END FrameStrobe_O[9]
  PIN N1BEG[0]
    DIRECTION OUTPUT ;
    USE SIGNAL ;
    ANTENNADIFFAREA 0.708600 ;
    PORT
      LAYER Metal2 ;
        RECT 49.240 218.840 49.640 219.240 ;
    END
  END N1BEG[0]
  PIN N1BEG[1]
    DIRECTION OUTPUT ;
    USE SIGNAL ;
    ANTENNADIFFAREA 0.708600 ;
    PORT
      LAYER Metal2 ;
        RECT 50.200 218.840 50.600 219.240 ;
    END
  END N1BEG[1]
  PIN N1BEG[2]
    DIRECTION OUTPUT ;
    USE SIGNAL ;
    ANTENNADIFFAREA 0.708600 ;
    PORT
      LAYER Metal2 ;
        RECT 51.160 218.840 51.560 219.240 ;
    END
  END N1BEG[2]
  PIN N1BEG[3]
    DIRECTION OUTPUT ;
    USE SIGNAL ;
    ANTENNADIFFAREA 0.708600 ;
    PORT
      LAYER Metal2 ;
        RECT 52.120 218.840 52.520 219.240 ;
    END
  END N1BEG[3]
  PIN N1END[0]
    DIRECTION INPUT ;
    USE SIGNAL ;
    ANTENNAGATEAREA 2.276600 ;
    PORT
      LAYER Metal2 ;
        RECT 49.240 0.000 49.640 0.400 ;
    END
  END N1END[0]
  PIN N1END[1]
    DIRECTION INPUT ;
    USE SIGNAL ;
    ANTENNAGATEAREA 2.169700 ;
    PORT
      LAYER Metal2 ;
        RECT 50.200 0.000 50.600 0.400 ;
    END
  END N1END[1]
  PIN N1END[2]
    DIRECTION INPUT ;
    USE SIGNAL ;
    ANTENNAGATEAREA 2.210800 ;
    PORT
      LAYER Metal2 ;
        RECT 51.160 0.000 51.560 0.400 ;
    END
  END N1END[2]
  PIN N1END[3]
    DIRECTION INPUT ;
    USE SIGNAL ;
    ANTENNAGATEAREA 2.132000 ;
    PORT
      LAYER Metal2 ;
        RECT 52.120 0.000 52.520 0.400 ;
    END
  END N1END[3]
  PIN N2BEG[0]
    DIRECTION OUTPUT ;
    USE SIGNAL ;
    ANTENNADIFFAREA 0.708600 ;
    PORT
      LAYER Metal2 ;
        RECT 53.080 218.840 53.480 219.240 ;
    END
  END N2BEG[0]
  PIN N2BEG[1]
    DIRECTION OUTPUT ;
    USE SIGNAL ;
    ANTENNADIFFAREA 0.708600 ;
    PORT
      LAYER Metal2 ;
        RECT 54.040 218.840 54.440 219.240 ;
    END
  END N2BEG[1]
  PIN N2BEG[2]
    DIRECTION OUTPUT ;
    USE SIGNAL ;
    ANTENNADIFFAREA 0.708600 ;
    PORT
      LAYER Metal2 ;
        RECT 55.000 218.840 55.400 219.240 ;
    END
  END N2BEG[2]
  PIN N2BEG[3]
    DIRECTION OUTPUT ;
    USE SIGNAL ;
    ANTENNADIFFAREA 0.708600 ;
    PORT
      LAYER Metal2 ;
        RECT 55.960 218.840 56.360 219.240 ;
    END
  END N2BEG[3]
  PIN N2BEG[4]
    DIRECTION OUTPUT ;
    USE SIGNAL ;
    ANTENNADIFFAREA 0.708600 ;
    PORT
      LAYER Metal2 ;
        RECT 56.920 218.840 57.320 219.240 ;
    END
  END N2BEG[4]
  PIN N2BEG[5]
    DIRECTION OUTPUT ;
    USE SIGNAL ;
    ANTENNADIFFAREA 0.708600 ;
    PORT
      LAYER Metal2 ;
        RECT 57.880 218.840 58.280 219.240 ;
    END
  END N2BEG[5]
  PIN N2BEG[6]
    DIRECTION OUTPUT ;
    USE SIGNAL ;
    ANTENNADIFFAREA 0.708600 ;
    PORT
      LAYER Metal2 ;
        RECT 58.840 218.840 59.240 219.240 ;
    END
  END N2BEG[6]
  PIN N2BEG[7]
    DIRECTION OUTPUT ;
    USE SIGNAL ;
    ANTENNADIFFAREA 0.708600 ;
    PORT
      LAYER Metal2 ;
        RECT 59.800 218.840 60.200 219.240 ;
    END
  END N2BEG[7]
  PIN N2BEGb[0]
    DIRECTION OUTPUT ;
    USE SIGNAL ;
    ANTENNADIFFAREA 0.708600 ;
    PORT
      LAYER Metal2 ;
        RECT 60.760 218.840 61.160 219.240 ;
    END
  END N2BEGb[0]
  PIN N2BEGb[1]
    DIRECTION OUTPUT ;
    USE SIGNAL ;
    ANTENNADIFFAREA 0.708600 ;
    PORT
      LAYER Metal2 ;
        RECT 61.720 218.840 62.120 219.240 ;
    END
  END N2BEGb[1]
  PIN N2BEGb[2]
    DIRECTION OUTPUT ;
    USE SIGNAL ;
    ANTENNADIFFAREA 0.708600 ;
    PORT
      LAYER Metal2 ;
        RECT 62.680 218.840 63.080 219.240 ;
    END
  END N2BEGb[2]
  PIN N2BEGb[3]
    DIRECTION OUTPUT ;
    USE SIGNAL ;
    ANTENNADIFFAREA 0.708600 ;
    PORT
      LAYER Metal2 ;
        RECT 63.640 218.840 64.040 219.240 ;
    END
  END N2BEGb[3]
  PIN N2BEGb[4]
    DIRECTION OUTPUT ;
    USE SIGNAL ;
    ANTENNADIFFAREA 0.708600 ;
    PORT
      LAYER Metal2 ;
        RECT 64.600 218.840 65.000 219.240 ;
    END
  END N2BEGb[4]
  PIN N2BEGb[5]
    DIRECTION OUTPUT ;
    USE SIGNAL ;
    ANTENNADIFFAREA 0.708600 ;
    PORT
      LAYER Metal2 ;
        RECT 65.560 218.840 65.960 219.240 ;
    END
  END N2BEGb[5]
  PIN N2BEGb[6]
    DIRECTION OUTPUT ;
    USE SIGNAL ;
    ANTENNADIFFAREA 0.708600 ;
    PORT
      LAYER Metal2 ;
        RECT 66.520 218.840 66.920 219.240 ;
    END
  END N2BEGb[6]
  PIN N2BEGb[7]
    DIRECTION OUTPUT ;
    USE SIGNAL ;
    ANTENNADIFFAREA 0.708600 ;
    PORT
      LAYER Metal2 ;
        RECT 67.480 218.840 67.880 219.240 ;
    END
  END N2BEGb[7]
  PIN N2END[0]
    DIRECTION INPUT ;
    USE SIGNAL ;
    ANTENNAGATEAREA 1.292200 ;
    PORT
      LAYER Metal2 ;
        RECT 60.760 0.000 61.160 0.400 ;
    END
  END N2END[0]
  PIN N2END[1]
    DIRECTION INPUT ;
    USE SIGNAL ;
    ANTENNAGATEAREA 1.079000 ;
    PORT
      LAYER Metal2 ;
        RECT 61.720 0.000 62.120 0.400 ;
    END
  END N2END[1]
  PIN N2END[2]
    DIRECTION INPUT ;
    USE SIGNAL ;
    ANTENNAGATEAREA 1.079000 ;
    PORT
      LAYER Metal2 ;
        RECT 62.680 0.000 63.080 0.400 ;
    END
  END N2END[2]
  PIN N2END[3]
    DIRECTION INPUT ;
    USE SIGNAL ;
    ANTENNAGATEAREA 1.349400 ;
    PORT
      LAYER Metal2 ;
        RECT 63.640 0.000 64.040 0.400 ;
    END
  END N2END[3]
  PIN N2END[4]
    DIRECTION INPUT ;
    USE SIGNAL ;
    ANTENNAGATEAREA 1.345000 ;
    PORT
      LAYER Metal2 ;
        RECT 64.600 0.000 65.000 0.400 ;
    END
  END N2END[4]
  PIN N2END[5]
    DIRECTION INPUT ;
    USE SIGNAL ;
    ANTENNAGATEAREA 1.046500 ;
    PORT
      LAYER Metal2 ;
        RECT 65.560 0.000 65.960 0.400 ;
    END
  END N2END[5]
  PIN N2END[6]
    DIRECTION INPUT ;
    USE SIGNAL ;
    ANTENNAGATEAREA 1.066000 ;
    PORT
      LAYER Metal2 ;
        RECT 66.520 0.000 66.920 0.400 ;
    END
  END N2END[6]
  PIN N2END[7]
    DIRECTION INPUT ;
    USE SIGNAL ;
    ANTENNAGATEAREA 1.279200 ;
    PORT
      LAYER Metal2 ;
        RECT 67.480 0.000 67.880 0.400 ;
    END
  END N2END[7]
  PIN N2MID[0]
    DIRECTION INPUT ;
    USE SIGNAL ;
    ANTENNAGATEAREA 0.833300 ;
    ANTENNADIFFAREA 8.061600 ;
    PORT
      LAYER Metal2 ;
        RECT 53.080 0.000 53.480 0.400 ;
    END
  END N2MID[0]
  PIN N2MID[1]
    DIRECTION INPUT ;
    USE SIGNAL ;
    ANTENNAGATEAREA 1.033500 ;
    ANTENNADIFFAREA 20.153999 ;
    PORT
      LAYER Metal2 ;
        RECT 54.040 0.000 54.440 0.400 ;
    END
  END N2MID[1]
  PIN N2MID[2]
    DIRECTION INPUT ;
    USE SIGNAL ;
    ANTENNAGATEAREA 0.820300 ;
    ANTENNADIFFAREA 20.153999 ;
    PORT
      LAYER Metal2 ;
        RECT 55.000 0.000 55.400 0.400 ;
    END
  END N2MID[2]
  PIN N2MID[3]
    DIRECTION INPUT ;
    USE SIGNAL ;
    ANTENNAGATEAREA 1.033500 ;
    PORT
      LAYER Metal2 ;
        RECT 55.960 0.000 56.360 0.400 ;
    END
  END N2MID[3]
  PIN N2MID[4]
    DIRECTION INPUT ;
    USE SIGNAL ;
    ANTENNAGATEAREA 0.820300 ;
    PORT
      LAYER Metal2 ;
        RECT 56.920 0.000 57.320 0.400 ;
    END
  END N2MID[4]
  PIN N2MID[5]
    DIRECTION INPUT ;
    USE SIGNAL ;
    ANTENNAGATEAREA 1.033500 ;
    ANTENNADIFFAREA 10.077000 ;
    PORT
      LAYER Metal2 ;
        RECT 57.880 0.000 58.280 0.400 ;
    END
  END N2MID[5]
  PIN N2MID[6]
    DIRECTION INPUT ;
    USE SIGNAL ;
    ANTENNAGATEAREA 0.820300 ;
    ANTENNADIFFAREA 8.061600 ;
    PORT
      LAYER Metal2 ;
        RECT 58.840 0.000 59.240 0.400 ;
    END
  END N2MID[6]
  PIN N2MID[7]
    DIRECTION INPUT ;
    USE SIGNAL ;
    ANTENNAGATEAREA 1.033500 ;
    ANTENNADIFFAREA 12.092400 ;
    PORT
      LAYER Metal2 ;
        RECT 59.800 0.000 60.200 0.400 ;
    END
  END N2MID[7]
  PIN N4BEG[0]
    DIRECTION OUTPUT ;
    USE SIGNAL ;
    ANTENNADIFFAREA 0.708600 ;
    PORT
      LAYER Metal2 ;
        RECT 68.440 218.840 68.840 219.240 ;
    END
  END N4BEG[0]
  PIN N4BEG[10]
    DIRECTION OUTPUT ;
    USE SIGNAL ;
    ANTENNADIFFAREA 0.708600 ;
    PORT
      LAYER Metal2 ;
        RECT 78.040 218.840 78.440 219.240 ;
    END
  END N4BEG[10]
  PIN N4BEG[11]
    DIRECTION OUTPUT ;
    USE SIGNAL ;
    ANTENNADIFFAREA 0.708600 ;
    PORT
      LAYER Metal2 ;
        RECT 79.000 218.840 79.400 219.240 ;
    END
  END N4BEG[11]
  PIN N4BEG[12]
    DIRECTION OUTPUT ;
    USE SIGNAL ;
    ANTENNADIFFAREA 0.708600 ;
    PORT
      LAYER Metal2 ;
        RECT 79.960 218.840 80.360 219.240 ;
    END
  END N4BEG[12]
  PIN N4BEG[13]
    DIRECTION OUTPUT ;
    USE SIGNAL ;
    ANTENNADIFFAREA 0.708600 ;
    PORT
      LAYER Metal2 ;
        RECT 80.920 218.840 81.320 219.240 ;
    END
  END N4BEG[13]
  PIN N4BEG[14]
    DIRECTION OUTPUT ;
    USE SIGNAL ;
    ANTENNADIFFAREA 0.708600 ;
    PORT
      LAYER Metal2 ;
        RECT 81.880 218.840 82.280 219.240 ;
    END
  END N4BEG[14]
  PIN N4BEG[15]
    DIRECTION OUTPUT ;
    USE SIGNAL ;
    ANTENNADIFFAREA 0.708600 ;
    PORT
      LAYER Metal2 ;
        RECT 82.840 218.840 83.240 219.240 ;
    END
  END N4BEG[15]
  PIN N4BEG[1]
    DIRECTION OUTPUT ;
    USE SIGNAL ;
    ANTENNADIFFAREA 0.708600 ;
    PORT
      LAYER Metal2 ;
        RECT 69.400 218.840 69.800 219.240 ;
    END
  END N4BEG[1]
  PIN N4BEG[2]
    DIRECTION OUTPUT ;
    USE SIGNAL ;
    ANTENNADIFFAREA 0.708600 ;
    PORT
      LAYER Metal2 ;
        RECT 70.360 218.840 70.760 219.240 ;
    END
  END N4BEG[2]
  PIN N4BEG[3]
    DIRECTION OUTPUT ;
    USE SIGNAL ;
    ANTENNADIFFAREA 0.708600 ;
    PORT
      LAYER Metal2 ;
        RECT 71.320 218.840 71.720 219.240 ;
    END
  END N4BEG[3]
  PIN N4BEG[4]
    DIRECTION OUTPUT ;
    USE SIGNAL ;
    ANTENNADIFFAREA 0.708600 ;
    PORT
      LAYER Metal2 ;
        RECT 72.280 218.840 72.680 219.240 ;
    END
  END N4BEG[4]
  PIN N4BEG[5]
    DIRECTION OUTPUT ;
    USE SIGNAL ;
    ANTENNADIFFAREA 0.708600 ;
    PORT
      LAYER Metal2 ;
        RECT 73.240 218.840 73.640 219.240 ;
    END
  END N4BEG[5]
  PIN N4BEG[6]
    DIRECTION OUTPUT ;
    USE SIGNAL ;
    ANTENNADIFFAREA 0.708600 ;
    PORT
      LAYER Metal2 ;
        RECT 74.200 218.840 74.600 219.240 ;
    END
  END N4BEG[6]
  PIN N4BEG[7]
    DIRECTION OUTPUT ;
    USE SIGNAL ;
    ANTENNADIFFAREA 0.708600 ;
    PORT
      LAYER Metal2 ;
        RECT 75.160 218.840 75.560 219.240 ;
    END
  END N4BEG[7]
  PIN N4BEG[8]
    DIRECTION OUTPUT ;
    USE SIGNAL ;
    ANTENNADIFFAREA 0.708600 ;
    PORT
      LAYER Metal2 ;
        RECT 76.120 218.840 76.520 219.240 ;
    END
  END N4BEG[8]
  PIN N4BEG[9]
    DIRECTION OUTPUT ;
    USE SIGNAL ;
    ANTENNADIFFAREA 0.708600 ;
    PORT
      LAYER Metal2 ;
        RECT 77.080 218.840 77.480 219.240 ;
    END
  END N4BEG[9]
  PIN N4END[0]
    DIRECTION INPUT ;
    USE SIGNAL ;
    ANTENNAGATEAREA 1.079000 ;
    PORT
      LAYER Metal2 ;
        RECT 68.440 0.000 68.840 0.400 ;
    END
  END N4END[0]
  PIN N4END[10]
    DIRECTION INPUT ;
    USE SIGNAL ;
    ANTENNAGATEAREA 0.180700 ;
    ANTENNADIFFAREA 2.015400 ;
    PORT
      LAYER Metal2 ;
        RECT 78.040 0.000 78.440 0.400 ;
    END
  END N4END[10]
  PIN N4END[11]
    DIRECTION INPUT ;
    USE SIGNAL ;
    ANTENNAGATEAREA 0.180700 ;
    ANTENNADIFFAREA 2.015400 ;
    PORT
      LAYER Metal2 ;
        RECT 79.000 0.000 79.400 0.400 ;
    END
  END N4END[11]
  PIN N4END[12]
    DIRECTION INPUT ;
    USE SIGNAL ;
    ANTENNAGATEAREA 0.180700 ;
    ANTENNADIFFAREA 2.015400 ;
    PORT
      LAYER Metal2 ;
        RECT 79.960 0.000 80.360 0.400 ;
    END
  END N4END[12]
  PIN N4END[13]
    DIRECTION INPUT ;
    USE SIGNAL ;
    ANTENNAGATEAREA 0.180700 ;
    ANTENNADIFFAREA 2.015400 ;
    PORT
      LAYER Metal2 ;
        RECT 80.920 0.000 81.320 0.400 ;
    END
  END N4END[13]
  PIN N4END[14]
    DIRECTION INPUT ;
    USE SIGNAL ;
    ANTENNAGATEAREA 0.180700 ;
    ANTENNADIFFAREA 2.015400 ;
    PORT
      LAYER Metal2 ;
        RECT 81.880 0.000 82.280 0.400 ;
    END
  END N4END[14]
  PIN N4END[15]
    DIRECTION INPUT ;
    USE SIGNAL ;
    ANTENNAGATEAREA 0.180700 ;
    ANTENNADIFFAREA 2.015400 ;
    PORT
      LAYER Metal2 ;
        RECT 82.840 0.000 83.240 0.400 ;
    END
  END N4END[15]
  PIN N4END[1]
    DIRECTION INPUT ;
    USE SIGNAL ;
    ANTENNAGATEAREA 1.079000 ;
    PORT
      LAYER Metal2 ;
        RECT 69.400 0.000 69.800 0.400 ;
    END
  END N4END[1]
  PIN N4END[2]
    DIRECTION INPUT ;
    USE SIGNAL ;
    ANTENNAGATEAREA 1.079000 ;
    PORT
      LAYER Metal2 ;
        RECT 70.360 0.000 70.760 0.400 ;
    END
  END N4END[2]
  PIN N4END[3]
    DIRECTION INPUT ;
    USE SIGNAL ;
    ANTENNAGATEAREA 1.092000 ;
    PORT
      LAYER Metal2 ;
        RECT 71.320 0.000 71.720 0.400 ;
    END
  END N4END[3]
  PIN N4END[4]
    DIRECTION INPUT ;
    USE SIGNAL ;
    ANTENNAGATEAREA 0.180700 ;
    ANTENNADIFFAREA 2.015400 ;
    PORT
      LAYER Metal2 ;
        RECT 72.280 0.000 72.680 0.400 ;
    END
  END N4END[4]
  PIN N4END[5]
    DIRECTION INPUT ;
    USE SIGNAL ;
    ANTENNAGATEAREA 0.180700 ;
    ANTENNADIFFAREA 2.015400 ;
    PORT
      LAYER Metal2 ;
        RECT 73.240 0.000 73.640 0.400 ;
    END
  END N4END[5]
  PIN N4END[6]
    DIRECTION INPUT ;
    USE SIGNAL ;
    ANTENNAGATEAREA 0.180700 ;
    ANTENNADIFFAREA 2.015400 ;
    PORT
      LAYER Metal2 ;
        RECT 74.200 0.000 74.600 0.400 ;
    END
  END N4END[6]
  PIN N4END[7]
    DIRECTION INPUT ;
    USE SIGNAL ;
    ANTENNAGATEAREA 0.180700 ;
    ANTENNADIFFAREA 2.015400 ;
    PORT
      LAYER Metal2 ;
        RECT 75.160 0.000 75.560 0.400 ;
    END
  END N4END[7]
  PIN N4END[8]
    DIRECTION INPUT ;
    USE SIGNAL ;
    ANTENNAGATEAREA 0.180700 ;
    ANTENNADIFFAREA 2.015400 ;
    PORT
      LAYER Metal2 ;
        RECT 76.120 0.000 76.520 0.400 ;
    END
  END N4END[8]
  PIN N4END[9]
    DIRECTION INPUT ;
    USE SIGNAL ;
    ANTENNAGATEAREA 0.180700 ;
    ANTENNADIFFAREA 2.015400 ;
    PORT
      LAYER Metal2 ;
        RECT 77.080 0.000 77.480 0.400 ;
    END
  END N4END[9]
  PIN NN4BEG[0]
    DIRECTION OUTPUT ;
    USE SIGNAL ;
    ANTENNADIFFAREA 0.708600 ;
    PORT
      LAYER Metal2 ;
        RECT 83.800 218.840 84.200 219.240 ;
    END
  END NN4BEG[0]
  PIN NN4BEG[10]
    DIRECTION OUTPUT ;
    USE SIGNAL ;
    ANTENNADIFFAREA 0.708600 ;
    PORT
      LAYER Metal2 ;
        RECT 93.400 218.840 93.800 219.240 ;
    END
  END NN4BEG[10]
  PIN NN4BEG[11]
    DIRECTION OUTPUT ;
    USE SIGNAL ;
    ANTENNADIFFAREA 0.708600 ;
    PORT
      LAYER Metal2 ;
        RECT 94.360 218.840 94.760 219.240 ;
    END
  END NN4BEG[11]
  PIN NN4BEG[12]
    DIRECTION OUTPUT ;
    USE SIGNAL ;
    ANTENNADIFFAREA 0.708600 ;
    PORT
      LAYER Metal2 ;
        RECT 95.320 218.840 95.720 219.240 ;
    END
  END NN4BEG[12]
  PIN NN4BEG[13]
    DIRECTION OUTPUT ;
    USE SIGNAL ;
    ANTENNADIFFAREA 0.708600 ;
    PORT
      LAYER Metal2 ;
        RECT 96.280 218.840 96.680 219.240 ;
    END
  END NN4BEG[13]
  PIN NN4BEG[14]
    DIRECTION OUTPUT ;
    USE SIGNAL ;
    ANTENNADIFFAREA 0.708600 ;
    PORT
      LAYER Metal2 ;
        RECT 97.240 218.840 97.640 219.240 ;
    END
  END NN4BEG[14]
  PIN NN4BEG[15]
    DIRECTION OUTPUT ;
    USE SIGNAL ;
    ANTENNADIFFAREA 0.708600 ;
    PORT
      LAYER Metal2 ;
        RECT 98.200 218.840 98.600 219.240 ;
    END
  END NN4BEG[15]
  PIN NN4BEG[1]
    DIRECTION OUTPUT ;
    USE SIGNAL ;
    ANTENNADIFFAREA 0.708600 ;
    PORT
      LAYER Metal2 ;
        RECT 84.760 218.840 85.160 219.240 ;
    END
  END NN4BEG[1]
  PIN NN4BEG[2]
    DIRECTION OUTPUT ;
    USE SIGNAL ;
    ANTENNADIFFAREA 0.708600 ;
    PORT
      LAYER Metal2 ;
        RECT 85.720 218.840 86.120 219.240 ;
    END
  END NN4BEG[2]
  PIN NN4BEG[3]
    DIRECTION OUTPUT ;
    USE SIGNAL ;
    ANTENNADIFFAREA 0.708600 ;
    PORT
      LAYER Metal2 ;
        RECT 86.680 218.840 87.080 219.240 ;
    END
  END NN4BEG[3]
  PIN NN4BEG[4]
    DIRECTION OUTPUT ;
    USE SIGNAL ;
    ANTENNADIFFAREA 0.708600 ;
    PORT
      LAYER Metal2 ;
        RECT 87.640 218.840 88.040 219.240 ;
    END
  END NN4BEG[4]
  PIN NN4BEG[5]
    DIRECTION OUTPUT ;
    USE SIGNAL ;
    ANTENNADIFFAREA 0.708600 ;
    PORT
      LAYER Metal2 ;
        RECT 88.600 218.840 89.000 219.240 ;
    END
  END NN4BEG[5]
  PIN NN4BEG[6]
    DIRECTION OUTPUT ;
    USE SIGNAL ;
    ANTENNADIFFAREA 0.708600 ;
    PORT
      LAYER Metal2 ;
        RECT 89.560 218.840 89.960 219.240 ;
    END
  END NN4BEG[6]
  PIN NN4BEG[7]
    DIRECTION OUTPUT ;
    USE SIGNAL ;
    ANTENNADIFFAREA 0.708600 ;
    PORT
      LAYER Metal2 ;
        RECT 90.520 218.840 90.920 219.240 ;
    END
  END NN4BEG[7]
  PIN NN4BEG[8]
    DIRECTION OUTPUT ;
    USE SIGNAL ;
    ANTENNADIFFAREA 0.708600 ;
    PORT
      LAYER Metal2 ;
        RECT 91.480 218.840 91.880 219.240 ;
    END
  END NN4BEG[8]
  PIN NN4BEG[9]
    DIRECTION OUTPUT ;
    USE SIGNAL ;
    ANTENNADIFFAREA 0.708600 ;
    PORT
      LAYER Metal2 ;
        RECT 92.440 218.840 92.840 219.240 ;
    END
  END NN4BEG[9]
  PIN NN4END[0]
    DIRECTION INPUT ;
    USE SIGNAL ;
    ANTENNAGATEAREA 0.652600 ;
    PORT
      LAYER Metal2 ;
        RECT 83.800 0.000 84.200 0.400 ;
    END
  END NN4END[0]
  PIN NN4END[10]
    DIRECTION INPUT ;
    USE SIGNAL ;
    ANTENNAGATEAREA 0.180700 ;
    ANTENNADIFFAREA 2.015400 ;
    PORT
      LAYER Metal2 ;
        RECT 93.400 0.000 93.800 0.400 ;
    END
  END NN4END[10]
  PIN NN4END[11]
    DIRECTION INPUT ;
    USE SIGNAL ;
    ANTENNAGATEAREA 0.180700 ;
    ANTENNADIFFAREA 2.015400 ;
    PORT
      LAYER Metal2 ;
        RECT 94.360 0.000 94.760 0.400 ;
    END
  END NN4END[11]
  PIN NN4END[12]
    DIRECTION INPUT ;
    USE SIGNAL ;
    ANTENNAGATEAREA 0.180700 ;
    ANTENNADIFFAREA 2.015400 ;
    PORT
      LAYER Metal2 ;
        RECT 95.320 0.000 95.720 0.400 ;
    END
  END NN4END[12]
  PIN NN4END[13]
    DIRECTION INPUT ;
    USE SIGNAL ;
    ANTENNAGATEAREA 0.180700 ;
    ANTENNADIFFAREA 4.030800 ;
    PORT
      LAYER Metal2 ;
        RECT 96.280 0.000 96.680 0.400 ;
    END
  END NN4END[13]
  PIN NN4END[14]
    DIRECTION INPUT ;
    USE SIGNAL ;
    ANTENNAGATEAREA 0.180700 ;
    ANTENNADIFFAREA 2.015400 ;
    PORT
      LAYER Metal2 ;
        RECT 97.240 0.000 97.640 0.400 ;
    END
  END NN4END[14]
  PIN NN4END[15]
    DIRECTION INPUT ;
    USE SIGNAL ;
    ANTENNAGATEAREA 0.180700 ;
    ANTENNADIFFAREA 2.015400 ;
    PORT
      LAYER Metal2 ;
        RECT 98.200 0.000 98.600 0.400 ;
    END
  END NN4END[15]
  PIN NN4END[1]
    DIRECTION INPUT ;
    USE SIGNAL ;
    ANTENNAGATEAREA 0.639600 ;
    PORT
      LAYER Metal2 ;
        RECT 84.760 0.000 85.160 0.400 ;
    END
  END NN4END[1]
  PIN NN4END[2]
    DIRECTION INPUT ;
    USE SIGNAL ;
    ANTENNAGATEAREA 0.668200 ;
    PORT
      LAYER Metal2 ;
        RECT 85.720 0.000 86.120 0.400 ;
    END
  END NN4END[2]
  PIN NN4END[3]
    DIRECTION INPUT ;
    USE SIGNAL ;
    ANTENNAGATEAREA 0.652600 ;
    PORT
      LAYER Metal2 ;
        RECT 86.680 0.000 87.080 0.400 ;
    END
  END NN4END[3]
  PIN NN4END[4]
    DIRECTION INPUT ;
    USE SIGNAL ;
    ANTENNAGATEAREA 0.180700 ;
    ANTENNADIFFAREA 2.015400 ;
    PORT
      LAYER Metal2 ;
        RECT 87.640 0.000 88.040 0.400 ;
    END
  END NN4END[4]
  PIN NN4END[5]
    DIRECTION INPUT ;
    USE SIGNAL ;
    ANTENNAGATEAREA 0.180700 ;
    ANTENNADIFFAREA 2.015400 ;
    PORT
      LAYER Metal2 ;
        RECT 88.600 0.000 89.000 0.400 ;
    END
  END NN4END[5]
  PIN NN4END[6]
    DIRECTION INPUT ;
    USE SIGNAL ;
    ANTENNAGATEAREA 0.180700 ;
    ANTENNADIFFAREA 2.015400 ;
    PORT
      LAYER Metal2 ;
        RECT 89.560 0.000 89.960 0.400 ;
    END
  END NN4END[6]
  PIN NN4END[7]
    DIRECTION INPUT ;
    USE SIGNAL ;
    ANTENNAGATEAREA 0.180700 ;
    ANTENNADIFFAREA 2.015400 ;
    PORT
      LAYER Metal2 ;
        RECT 90.520 0.000 90.920 0.400 ;
    END
  END NN4END[7]
  PIN NN4END[8]
    DIRECTION INPUT ;
    USE SIGNAL ;
    ANTENNAGATEAREA 0.180700 ;
    ANTENNADIFFAREA 2.015400 ;
    PORT
      LAYER Metal2 ;
        RECT 91.480 0.000 91.880 0.400 ;
    END
  END NN4END[8]
  PIN NN4END[9]
    DIRECTION INPUT ;
    USE SIGNAL ;
    ANTENNAGATEAREA 0.180700 ;
    ANTENNADIFFAREA 2.015400 ;
    PORT
      LAYER Metal2 ;
        RECT 92.440 0.000 92.840 0.400 ;
    END
  END NN4END[9]
  PIN S1BEG[0]
    DIRECTION OUTPUT ;
    USE SIGNAL ;
    ANTENNADIFFAREA 0.708600 ;
    PORT
      LAYER Metal2 ;
        RECT 100.120 0.000 100.520 0.400 ;
    END
  END S1BEG[0]
  PIN S1BEG[1]
    DIRECTION OUTPUT ;
    USE SIGNAL ;
    ANTENNADIFFAREA 0.708600 ;
    PORT
      LAYER Metal2 ;
        RECT 101.080 0.000 101.480 0.400 ;
    END
  END S1BEG[1]
  PIN S1BEG[2]
    DIRECTION OUTPUT ;
    USE SIGNAL ;
    ANTENNADIFFAREA 0.708600 ;
    PORT
      LAYER Metal2 ;
        RECT 102.040 0.000 102.440 0.400 ;
    END
  END S1BEG[2]
  PIN S1BEG[3]
    DIRECTION OUTPUT ;
    USE SIGNAL ;
    ANTENNADIFFAREA 0.708600 ;
    PORT
      LAYER Metal2 ;
        RECT 103.000 0.000 103.400 0.400 ;
    END
  END S1BEG[3]
  PIN S1END[0]
    DIRECTION INPUT ;
    USE SIGNAL ;
    ANTENNAGATEAREA 1.705600 ;
    PORT
      LAYER Metal2 ;
        RECT 100.120 218.840 100.520 219.240 ;
    END
  END S1END[0]
  PIN S1END[1]
    DIRECTION INPUT ;
    USE SIGNAL ;
    ANTENNAGATEAREA 1.747200 ;
    PORT
      LAYER Metal2 ;
        RECT 101.080 218.840 101.480 219.240 ;
    END
  END S1END[1]
  PIN S1END[2]
    DIRECTION INPUT ;
    USE SIGNAL ;
    ANTENNAGATEAREA 1.734200 ;
    PORT
      LAYER Metal2 ;
        RECT 102.040 218.840 102.440 219.240 ;
    END
  END S1END[2]
  PIN S1END[3]
    DIRECTION INPUT ;
    USE SIGNAL ;
    ANTENNAGATEAREA 1.718600 ;
    PORT
      LAYER Metal2 ;
        RECT 103.000 218.840 103.400 219.240 ;
    END
  END S1END[3]
  PIN S2BEG[0]
    DIRECTION OUTPUT ;
    USE SIGNAL ;
    ANTENNADIFFAREA 0.708600 ;
    PORT
      LAYER Metal2 ;
        RECT 103.960 0.000 104.360 0.400 ;
    END
  END S2BEG[0]
  PIN S2BEG[1]
    DIRECTION OUTPUT ;
    USE SIGNAL ;
    ANTENNADIFFAREA 0.708600 ;
    PORT
      LAYER Metal2 ;
        RECT 104.920 0.000 105.320 0.400 ;
    END
  END S2BEG[1]
  PIN S2BEG[2]
    DIRECTION OUTPUT ;
    USE SIGNAL ;
    ANTENNADIFFAREA 0.708600 ;
    PORT
      LAYER Metal2 ;
        RECT 105.880 0.000 106.280 0.400 ;
    END
  END S2BEG[2]
  PIN S2BEG[3]
    DIRECTION OUTPUT ;
    USE SIGNAL ;
    ANTENNADIFFAREA 0.708600 ;
    PORT
      LAYER Metal2 ;
        RECT 106.840 0.000 107.240 0.400 ;
    END
  END S2BEG[3]
  PIN S2BEG[4]
    DIRECTION OUTPUT ;
    USE SIGNAL ;
    ANTENNADIFFAREA 0.708600 ;
    PORT
      LAYER Metal2 ;
        RECT 107.800 0.000 108.200 0.400 ;
    END
  END S2BEG[4]
  PIN S2BEG[5]
    DIRECTION OUTPUT ;
    USE SIGNAL ;
    ANTENNADIFFAREA 0.708600 ;
    PORT
      LAYER Metal2 ;
        RECT 108.760 0.000 109.160 0.400 ;
    END
  END S2BEG[5]
  PIN S2BEG[6]
    DIRECTION OUTPUT ;
    USE SIGNAL ;
    ANTENNADIFFAREA 0.708600 ;
    PORT
      LAYER Metal2 ;
        RECT 109.720 0.000 110.120 0.400 ;
    END
  END S2BEG[6]
  PIN S2BEG[7]
    DIRECTION OUTPUT ;
    USE SIGNAL ;
    ANTENNADIFFAREA 0.708600 ;
    PORT
      LAYER Metal2 ;
        RECT 110.680 0.000 111.080 0.400 ;
    END
  END S2BEG[7]
  PIN S2BEGb[0]
    DIRECTION OUTPUT ;
    USE SIGNAL ;
    ANTENNADIFFAREA 0.708600 ;
    PORT
      LAYER Metal2 ;
        RECT 111.640 0.000 112.040 0.400 ;
    END
  END S2BEGb[0]
  PIN S2BEGb[1]
    DIRECTION OUTPUT ;
    USE SIGNAL ;
    ANTENNADIFFAREA 0.708600 ;
    PORT
      LAYER Metal2 ;
        RECT 112.600 0.000 113.000 0.400 ;
    END
  END S2BEGb[1]
  PIN S2BEGb[2]
    DIRECTION OUTPUT ;
    USE SIGNAL ;
    ANTENNADIFFAREA 0.708600 ;
    PORT
      LAYER Metal2 ;
        RECT 113.560 0.000 113.960 0.400 ;
    END
  END S2BEGb[2]
  PIN S2BEGb[3]
    DIRECTION OUTPUT ;
    USE SIGNAL ;
    ANTENNADIFFAREA 0.708600 ;
    PORT
      LAYER Metal2 ;
        RECT 114.520 0.000 114.920 0.400 ;
    END
  END S2BEGb[3]
  PIN S2BEGb[4]
    DIRECTION OUTPUT ;
    USE SIGNAL ;
    ANTENNADIFFAREA 0.708600 ;
    PORT
      LAYER Metal2 ;
        RECT 115.480 0.000 115.880 0.400 ;
    END
  END S2BEGb[4]
  PIN S2BEGb[5]
    DIRECTION OUTPUT ;
    USE SIGNAL ;
    ANTENNADIFFAREA 0.708600 ;
    PORT
      LAYER Metal2 ;
        RECT 116.440 0.000 116.840 0.400 ;
    END
  END S2BEGb[5]
  PIN S2BEGb[6]
    DIRECTION OUTPUT ;
    USE SIGNAL ;
    ANTENNADIFFAREA 0.708600 ;
    PORT
      LAYER Metal2 ;
        RECT 117.400 0.000 117.800 0.400 ;
    END
  END S2BEGb[6]
  PIN S2BEGb[7]
    DIRECTION OUTPUT ;
    USE SIGNAL ;
    ANTENNADIFFAREA 0.708600 ;
    PORT
      LAYER Metal2 ;
        RECT 118.360 0.000 118.760 0.400 ;
    END
  END S2BEGb[7]
  PIN S2END[0]
    DIRECTION INPUT ;
    USE SIGNAL ;
    ANTENNAGATEAREA 1.320800 ;
    PORT
      LAYER Metal2 ;
        RECT 111.640 218.840 112.040 219.240 ;
    END
  END S2END[0]
  PIN S2END[1]
    DIRECTION INPUT ;
    USE SIGNAL ;
    ANTENNAGATEAREA 1.307800 ;
    PORT
      LAYER Metal2 ;
        RECT 112.600 218.840 113.000 219.240 ;
    END
  END S2END[1]
  PIN S2END[2]
    DIRECTION INPUT ;
    USE SIGNAL ;
    ANTENNAGATEAREA 1.320800 ;
    PORT
      LAYER Metal2 ;
        RECT 113.560 218.840 113.960 219.240 ;
    END
  END S2END[2]
  PIN S2END[3]
    DIRECTION INPUT ;
    USE SIGNAL ;
    ANTENNAGATEAREA 1.071200 ;
    PORT
      LAYER Metal2 ;
        RECT 114.520 218.840 114.920 219.240 ;
    END
  END S2END[3]
  PIN S2END[4]
    DIRECTION INPUT ;
    USE SIGNAL ;
    ANTENNAGATEAREA 1.079000 ;
    PORT
      LAYER Metal2 ;
        RECT 115.480 218.840 115.880 219.240 ;
    END
  END S2END[4]
  PIN S2END[5]
    DIRECTION INPUT ;
    USE SIGNAL ;
    ANTENNAGATEAREA 1.173400 ;
    PORT
      LAYER Metal2 ;
        RECT 116.440 218.840 116.840 219.240 ;
    END
  END S2END[5]
  PIN S2END[6]
    DIRECTION INPUT ;
    USE SIGNAL ;
    ANTENNAGATEAREA 1.079000 ;
    PORT
      LAYER Metal2 ;
        RECT 117.400 218.840 117.800 219.240 ;
    END
  END S2END[6]
  PIN S2END[7]
    DIRECTION INPUT ;
    USE SIGNAL ;
    ANTENNAGATEAREA 1.305200 ;
    PORT
      LAYER Metal2 ;
        RECT 118.360 218.840 118.760 219.240 ;
    END
  END S2END[7]
  PIN S2MID[0]
    DIRECTION INPUT ;
    USE SIGNAL ;
    ANTENNAGATEAREA 0.833300 ;
    PORT
      LAYER Metal2 ;
        RECT 103.960 218.840 104.360 219.240 ;
    END
  END S2MID[0]
  PIN S2MID[1]
    DIRECTION INPUT ;
    USE SIGNAL ;
    ANTENNAGATEAREA 1.033500 ;
    PORT
      LAYER Metal2 ;
        RECT 104.920 218.840 105.320 219.240 ;
    END
  END S2MID[1]
  PIN S2MID[2]
    DIRECTION INPUT ;
    USE SIGNAL ;
    ANTENNAGATEAREA 0.848900 ;
    PORT
      LAYER Metal2 ;
        RECT 105.880 218.840 106.280 219.240 ;
    END
  END S2MID[2]
  PIN S2MID[3]
    DIRECTION INPUT ;
    USE SIGNAL ;
    ANTENNAGATEAREA 1.033500 ;
    PORT
      LAYER Metal2 ;
        RECT 106.840 218.840 107.240 219.240 ;
    END
  END S2MID[3]
  PIN S2MID[4]
    DIRECTION INPUT ;
    USE SIGNAL ;
    ANTENNAGATEAREA 0.820300 ;
    PORT
      LAYER Metal2 ;
        RECT 107.800 218.840 108.200 219.240 ;
    END
  END S2MID[4]
  PIN S2MID[5]
    DIRECTION INPUT ;
    USE SIGNAL ;
    ANTENNAGATEAREA 1.033500 ;
    PORT
      LAYER Metal2 ;
        RECT 108.760 218.840 109.160 219.240 ;
    END
  END S2MID[5]
  PIN S2MID[6]
    DIRECTION INPUT ;
    USE SIGNAL ;
    ANTENNAGATEAREA 0.820300 ;
    PORT
      LAYER Metal2 ;
        RECT 109.720 218.840 110.120 219.240 ;
    END
  END S2MID[6]
  PIN S2MID[7]
    DIRECTION INPUT ;
    USE SIGNAL ;
    ANTENNAGATEAREA 1.033500 ;
    PORT
      LAYER Metal2 ;
        RECT 110.680 218.840 111.080 219.240 ;
    END
  END S2MID[7]
  PIN S4BEG[0]
    DIRECTION OUTPUT ;
    USE SIGNAL ;
    ANTENNADIFFAREA 0.708600 ;
    PORT
      LAYER Metal2 ;
        RECT 119.320 0.000 119.720 0.400 ;
    END
  END S4BEG[0]
  PIN S4BEG[10]
    DIRECTION OUTPUT ;
    USE SIGNAL ;
    ANTENNADIFFAREA 0.708600 ;
    PORT
      LAYER Metal2 ;
        RECT 128.920 0.000 129.320 0.400 ;
    END
  END S4BEG[10]
  PIN S4BEG[11]
    DIRECTION OUTPUT ;
    USE SIGNAL ;
    ANTENNADIFFAREA 0.708600 ;
    PORT
      LAYER Metal2 ;
        RECT 129.880 0.000 130.280 0.400 ;
    END
  END S4BEG[11]
  PIN S4BEG[12]
    DIRECTION OUTPUT ;
    USE SIGNAL ;
    ANTENNADIFFAREA 0.708600 ;
    PORT
      LAYER Metal2 ;
        RECT 130.840 0.000 131.240 0.400 ;
    END
  END S4BEG[12]
  PIN S4BEG[13]
    DIRECTION OUTPUT ;
    USE SIGNAL ;
    ANTENNADIFFAREA 0.708600 ;
    PORT
      LAYER Metal2 ;
        RECT 131.800 0.000 132.200 0.400 ;
    END
  END S4BEG[13]
  PIN S4BEG[14]
    DIRECTION OUTPUT ;
    USE SIGNAL ;
    ANTENNADIFFAREA 0.708600 ;
    PORT
      LAYER Metal2 ;
        RECT 132.760 0.000 133.160 0.400 ;
    END
  END S4BEG[14]
  PIN S4BEG[15]
    DIRECTION OUTPUT ;
    USE SIGNAL ;
    ANTENNADIFFAREA 0.708600 ;
    PORT
      LAYER Metal2 ;
        RECT 133.720 0.000 134.120 0.400 ;
    END
  END S4BEG[15]
  PIN S4BEG[1]
    DIRECTION OUTPUT ;
    USE SIGNAL ;
    ANTENNADIFFAREA 0.708600 ;
    PORT
      LAYER Metal2 ;
        RECT 120.280 0.000 120.680 0.400 ;
    END
  END S4BEG[1]
  PIN S4BEG[2]
    DIRECTION OUTPUT ;
    USE SIGNAL ;
    ANTENNADIFFAREA 0.708600 ;
    PORT
      LAYER Metal2 ;
        RECT 121.240 0.000 121.640 0.400 ;
    END
  END S4BEG[2]
  PIN S4BEG[3]
    DIRECTION OUTPUT ;
    USE SIGNAL ;
    ANTENNADIFFAREA 0.708600 ;
    PORT
      LAYER Metal2 ;
        RECT 122.200 0.000 122.600 0.400 ;
    END
  END S4BEG[3]
  PIN S4BEG[4]
    DIRECTION OUTPUT ;
    USE SIGNAL ;
    ANTENNADIFFAREA 0.708600 ;
    PORT
      LAYER Metal2 ;
        RECT 123.160 0.000 123.560 0.400 ;
    END
  END S4BEG[4]
  PIN S4BEG[5]
    DIRECTION OUTPUT ;
    USE SIGNAL ;
    ANTENNADIFFAREA 0.708600 ;
    PORT
      LAYER Metal2 ;
        RECT 124.120 0.000 124.520 0.400 ;
    END
  END S4BEG[5]
  PIN S4BEG[6]
    DIRECTION OUTPUT ;
    USE SIGNAL ;
    ANTENNADIFFAREA 0.708600 ;
    PORT
      LAYER Metal2 ;
        RECT 125.080 0.000 125.480 0.400 ;
    END
  END S4BEG[6]
  PIN S4BEG[7]
    DIRECTION OUTPUT ;
    USE SIGNAL ;
    ANTENNADIFFAREA 0.708600 ;
    PORT
      LAYER Metal2 ;
        RECT 126.040 0.000 126.440 0.400 ;
    END
  END S4BEG[7]
  PIN S4BEG[8]
    DIRECTION OUTPUT ;
    USE SIGNAL ;
    ANTENNADIFFAREA 0.708600 ;
    PORT
      LAYER Metal2 ;
        RECT 127.000 0.000 127.400 0.400 ;
    END
  END S4BEG[8]
  PIN S4BEG[9]
    DIRECTION OUTPUT ;
    USE SIGNAL ;
    ANTENNADIFFAREA 0.708600 ;
    PORT
      LAYER Metal2 ;
        RECT 127.960 0.000 128.360 0.400 ;
    END
  END S4BEG[9]
  PIN S4END[0]
    DIRECTION INPUT ;
    USE SIGNAL ;
    ANTENNAGATEAREA 1.046500 ;
    PORT
      LAYER Metal2 ;
        RECT 119.320 218.840 119.720 219.240 ;
    END
  END S4END[0]
  PIN S4END[10]
    DIRECTION INPUT ;
    USE SIGNAL ;
    ANTENNAGATEAREA 0.180700 ;
    PORT
      LAYER Metal2 ;
        RECT 128.920 218.840 129.320 219.240 ;
    END
  END S4END[10]
  PIN S4END[11]
    DIRECTION INPUT ;
    USE SIGNAL ;
    ANTENNAGATEAREA 0.180700 ;
    PORT
      LAYER Metal2 ;
        RECT 129.880 218.840 130.280 219.240 ;
    END
  END S4END[11]
  PIN S4END[12]
    DIRECTION INPUT ;
    USE SIGNAL ;
    ANTENNAGATEAREA 0.180700 ;
    PORT
      LAYER Metal2 ;
        RECT 130.840 218.840 131.240 219.240 ;
    END
  END S4END[12]
  PIN S4END[13]
    DIRECTION INPUT ;
    USE SIGNAL ;
    ANTENNAGATEAREA 0.180700 ;
    PORT
      LAYER Metal2 ;
        RECT 131.800 218.840 132.200 219.240 ;
    END
  END S4END[13]
  PIN S4END[14]
    DIRECTION INPUT ;
    USE SIGNAL ;
    ANTENNAGATEAREA 0.180700 ;
    PORT
      LAYER Metal2 ;
        RECT 132.760 218.840 133.160 219.240 ;
    END
  END S4END[14]
  PIN S4END[15]
    DIRECTION INPUT ;
    USE SIGNAL ;
    ANTENNAGATEAREA 0.180700 ;
    PORT
      LAYER Metal2 ;
        RECT 133.720 218.840 134.120 219.240 ;
    END
  END S4END[15]
  PIN S4END[1]
    DIRECTION INPUT ;
    USE SIGNAL ;
    ANTENNAGATEAREA 1.066000 ;
    PORT
      LAYER Metal2 ;
        RECT 120.280 218.840 120.680 219.240 ;
    END
  END S4END[1]
  PIN S4END[2]
    DIRECTION INPUT ;
    USE SIGNAL ;
    ANTENNAGATEAREA 1.136200 ;
    PORT
      LAYER Metal2 ;
        RECT 121.240 218.840 121.640 219.240 ;
    END
  END S4END[2]
  PIN S4END[3]
    DIRECTION INPUT ;
    USE SIGNAL ;
    ANTENNAGATEAREA 1.107600 ;
    PORT
      LAYER Metal2 ;
        RECT 122.200 218.840 122.600 219.240 ;
    END
  END S4END[3]
  PIN S4END[4]
    DIRECTION INPUT ;
    USE SIGNAL ;
    ANTENNAGATEAREA 0.180700 ;
    PORT
      LAYER Metal2 ;
        RECT 123.160 218.840 123.560 219.240 ;
    END
  END S4END[4]
  PIN S4END[5]
    DIRECTION INPUT ;
    USE SIGNAL ;
    ANTENNAGATEAREA 0.180700 ;
    PORT
      LAYER Metal2 ;
        RECT 124.120 218.840 124.520 219.240 ;
    END
  END S4END[5]
  PIN S4END[6]
    DIRECTION INPUT ;
    USE SIGNAL ;
    ANTENNAGATEAREA 0.180700 ;
    PORT
      LAYER Metal2 ;
        RECT 125.080 218.840 125.480 219.240 ;
    END
  END S4END[6]
  PIN S4END[7]
    DIRECTION INPUT ;
    USE SIGNAL ;
    ANTENNAGATEAREA 0.180700 ;
    PORT
      LAYER Metal2 ;
        RECT 126.040 218.840 126.440 219.240 ;
    END
  END S4END[7]
  PIN S4END[8]
    DIRECTION INPUT ;
    USE SIGNAL ;
    ANTENNAGATEAREA 0.180700 ;
    PORT
      LAYER Metal2 ;
        RECT 127.000 218.840 127.400 219.240 ;
    END
  END S4END[8]
  PIN S4END[9]
    DIRECTION INPUT ;
    USE SIGNAL ;
    ANTENNAGATEAREA 0.180700 ;
    PORT
      LAYER Metal2 ;
        RECT 127.960 218.840 128.360 219.240 ;
    END
  END S4END[9]
  PIN SS4BEG[0]
    DIRECTION OUTPUT ;
    USE SIGNAL ;
    ANTENNADIFFAREA 0.708600 ;
    PORT
      LAYER Metal2 ;
        RECT 134.680 0.000 135.080 0.400 ;
    END
  END SS4BEG[0]
  PIN SS4BEG[10]
    DIRECTION OUTPUT ;
    USE SIGNAL ;
    ANTENNADIFFAREA 0.708600 ;
    PORT
      LAYER Metal2 ;
        RECT 144.280 0.000 144.680 0.400 ;
    END
  END SS4BEG[10]
  PIN SS4BEG[11]
    DIRECTION OUTPUT ;
    USE SIGNAL ;
    ANTENNADIFFAREA 0.708600 ;
    PORT
      LAYER Metal2 ;
        RECT 145.240 0.000 145.640 0.400 ;
    END
  END SS4BEG[11]
  PIN SS4BEG[12]
    DIRECTION OUTPUT ;
    USE SIGNAL ;
    ANTENNADIFFAREA 0.708600 ;
    PORT
      LAYER Metal2 ;
        RECT 146.200 0.000 146.600 0.400 ;
    END
  END SS4BEG[12]
  PIN SS4BEG[13]
    DIRECTION OUTPUT ;
    USE SIGNAL ;
    ANTENNADIFFAREA 0.708600 ;
    PORT
      LAYER Metal2 ;
        RECT 147.160 0.000 147.560 0.400 ;
    END
  END SS4BEG[13]
  PIN SS4BEG[14]
    DIRECTION OUTPUT ;
    USE SIGNAL ;
    ANTENNADIFFAREA 0.708600 ;
    PORT
      LAYER Metal2 ;
        RECT 148.120 0.000 148.520 0.400 ;
    END
  END SS4BEG[14]
  PIN SS4BEG[15]
    DIRECTION OUTPUT ;
    USE SIGNAL ;
    ANTENNADIFFAREA 0.708600 ;
    PORT
      LAYER Metal2 ;
        RECT 149.080 0.000 149.480 0.400 ;
    END
  END SS4BEG[15]
  PIN SS4BEG[1]
    DIRECTION OUTPUT ;
    USE SIGNAL ;
    ANTENNADIFFAREA 0.708600 ;
    PORT
      LAYER Metal2 ;
        RECT 135.640 0.000 136.040 0.400 ;
    END
  END SS4BEG[1]
  PIN SS4BEG[2]
    DIRECTION OUTPUT ;
    USE SIGNAL ;
    ANTENNADIFFAREA 0.708600 ;
    PORT
      LAYER Metal2 ;
        RECT 136.600 0.000 137.000 0.400 ;
    END
  END SS4BEG[2]
  PIN SS4BEG[3]
    DIRECTION OUTPUT ;
    USE SIGNAL ;
    ANTENNADIFFAREA 0.708600 ;
    PORT
      LAYER Metal2 ;
        RECT 137.560 0.000 137.960 0.400 ;
    END
  END SS4BEG[3]
  PIN SS4BEG[4]
    DIRECTION OUTPUT ;
    USE SIGNAL ;
    ANTENNADIFFAREA 0.708600 ;
    PORT
      LAYER Metal2 ;
        RECT 138.520 0.000 138.920 0.400 ;
    END
  END SS4BEG[4]
  PIN SS4BEG[5]
    DIRECTION OUTPUT ;
    USE SIGNAL ;
    ANTENNADIFFAREA 0.708600 ;
    PORT
      LAYER Metal2 ;
        RECT 139.480 0.000 139.880 0.400 ;
    END
  END SS4BEG[5]
  PIN SS4BEG[6]
    DIRECTION OUTPUT ;
    USE SIGNAL ;
    ANTENNADIFFAREA 0.708600 ;
    PORT
      LAYER Metal2 ;
        RECT 140.440 0.000 140.840 0.400 ;
    END
  END SS4BEG[6]
  PIN SS4BEG[7]
    DIRECTION OUTPUT ;
    USE SIGNAL ;
    ANTENNADIFFAREA 0.708600 ;
    PORT
      LAYER Metal2 ;
        RECT 141.400 0.000 141.800 0.400 ;
    END
  END SS4BEG[7]
  PIN SS4BEG[8]
    DIRECTION OUTPUT ;
    USE SIGNAL ;
    ANTENNADIFFAREA 0.708600 ;
    PORT
      LAYER Metal2 ;
        RECT 142.360 0.000 142.760 0.400 ;
    END
  END SS4BEG[8]
  PIN SS4BEG[9]
    DIRECTION OUTPUT ;
    USE SIGNAL ;
    ANTENNADIFFAREA 0.708600 ;
    PORT
      LAYER Metal2 ;
        RECT 143.320 0.000 143.720 0.400 ;
    END
  END SS4BEG[9]
  PIN SS4END[0]
    DIRECTION INPUT ;
    USE SIGNAL ;
    ANTENNAGATEAREA 0.681200 ;
    PORT
      LAYER Metal2 ;
        RECT 134.680 218.840 135.080 219.240 ;
    END
  END SS4END[0]
  PIN SS4END[10]
    DIRECTION INPUT ;
    USE SIGNAL ;
    ANTENNAGATEAREA 0.180700 ;
    PORT
      LAYER Metal2 ;
        RECT 144.280 218.840 144.680 219.240 ;
    END
  END SS4END[10]
  PIN SS4END[11]
    DIRECTION INPUT ;
    USE SIGNAL ;
    ANTENNAGATEAREA 0.180700 ;
    PORT
      LAYER Metal2 ;
        RECT 145.240 218.840 145.640 219.240 ;
    END
  END SS4END[11]
  PIN SS4END[12]
    DIRECTION INPUT ;
    USE SIGNAL ;
    ANTENNAGATEAREA 0.180700 ;
    PORT
      LAYER Metal2 ;
        RECT 146.200 218.840 146.600 219.240 ;
    END
  END SS4END[12]
  PIN SS4END[13]
    DIRECTION INPUT ;
    USE SIGNAL ;
    ANTENNAGATEAREA 0.180700 ;
    PORT
      LAYER Metal2 ;
        RECT 147.160 218.840 147.560 219.240 ;
    END
  END SS4END[13]
  PIN SS4END[14]
    DIRECTION INPUT ;
    USE SIGNAL ;
    ANTENNAGATEAREA 0.180700 ;
    PORT
      LAYER Metal2 ;
        RECT 148.120 218.840 148.520 219.240 ;
    END
  END SS4END[14]
  PIN SS4END[15]
    DIRECTION INPUT ;
    USE SIGNAL ;
    ANTENNAGATEAREA 0.180700 ;
    ANTENNADIFFAREA 2.015400 ;
    PORT
      LAYER Metal2 ;
        RECT 149.080 218.840 149.480 219.240 ;
    END
  END SS4END[15]
  PIN SS4END[1]
    DIRECTION INPUT ;
    USE SIGNAL ;
    ANTENNAGATEAREA 0.639600 ;
    PORT
      LAYER Metal2 ;
        RECT 135.640 218.840 136.040 219.240 ;
    END
  END SS4END[1]
  PIN SS4END[2]
    DIRECTION INPUT ;
    USE SIGNAL ;
    ANTENNAGATEAREA 0.618800 ;
    PORT
      LAYER Metal2 ;
        RECT 136.600 218.840 137.000 219.240 ;
    END
  END SS4END[2]
  PIN SS4END[3]
    DIRECTION INPUT ;
    USE SIGNAL ;
    ANTENNAGATEAREA 0.647400 ;
    PORT
      LAYER Metal2 ;
        RECT 137.560 218.840 137.960 219.240 ;
    END
  END SS4END[3]
  PIN SS4END[4]
    DIRECTION INPUT ;
    USE SIGNAL ;
    ANTENNAGATEAREA 0.180700 ;
    PORT
      LAYER Metal2 ;
        RECT 138.520 218.840 138.920 219.240 ;
    END
  END SS4END[4]
  PIN SS4END[5]
    DIRECTION INPUT ;
    USE SIGNAL ;
    ANTENNAGATEAREA 0.180700 ;
    PORT
      LAYER Metal2 ;
        RECT 139.480 218.840 139.880 219.240 ;
    END
  END SS4END[5]
  PIN SS4END[6]
    DIRECTION INPUT ;
    USE SIGNAL ;
    ANTENNAGATEAREA 0.180700 ;
    PORT
      LAYER Metal2 ;
        RECT 140.440 218.840 140.840 219.240 ;
    END
  END SS4END[6]
  PIN SS4END[7]
    DIRECTION INPUT ;
    USE SIGNAL ;
    ANTENNAGATEAREA 0.180700 ;
    PORT
      LAYER Metal2 ;
        RECT 141.400 218.840 141.800 219.240 ;
    END
  END SS4END[7]
  PIN SS4END[8]
    DIRECTION INPUT ;
    USE SIGNAL ;
    ANTENNAGATEAREA 0.180700 ;
    PORT
      LAYER Metal2 ;
        RECT 142.360 218.840 142.760 219.240 ;
    END
  END SS4END[8]
  PIN SS4END[9]
    DIRECTION INPUT ;
    USE SIGNAL ;
    ANTENNAGATEAREA 0.180700 ;
    PORT
      LAYER Metal2 ;
        RECT 143.320 218.840 143.720 219.240 ;
    END
  END SS4END[9]
  PIN UserCLK
    DIRECTION INPUT ;
    USE SIGNAL ;
    ANTENNAGATEAREA 1.450800 ;
    PORT
      LAYER Metal2 ;
        RECT 169.240 0.000 169.640 0.400 ;
    END
  END UserCLK
  PIN UserCLKo
    DIRECTION OUTPUT ;
    USE SIGNAL ;
    ANTENNADIFFAREA 0.708600 ;
    PORT
      LAYER Metal2 ;
        RECT 169.240 218.840 169.640 219.240 ;
    END
  END UserCLKo
  PIN VGND
    DIRECTION INOUT ;
    USE GROUND ;
    PORT
      LAYER Metal4 ;
        RECT 21.580 0.000 23.780 219.240 ;
    END
    PORT
      LAYER Metal4 ;
        RECT 97.180 0.000 99.380 219.240 ;
    END
    PORT
      LAYER Metal4 ;
        RECT 172.780 0.000 174.980 219.240 ;
    END
  END VGND
  PIN VPWR
    DIRECTION INOUT ;
    USE POWER ;
    PORT
      LAYER Metal4 ;
        RECT 15.380 0.000 17.580 219.240 ;
    END
    PORT
      LAYER Metal4 ;
        RECT 90.980 0.000 93.180 219.240 ;
    END
    PORT
      LAYER Metal4 ;
        RECT 166.580 0.000 168.780 219.240 ;
    END
  END VPWR
  PIN W1BEG[0]
    DIRECTION OUTPUT ;
    USE SIGNAL ;
    ANTENNADIFFAREA 0.708600 ;
    PORT
      LAYER Metal3 ;
        RECT 0.000 2.740 0.400 3.140 ;
    END
  END W1BEG[0]
  PIN W1BEG[1]
    DIRECTION OUTPUT ;
    USE SIGNAL ;
    ANTENNADIFFAREA 0.708600 ;
    PORT
      LAYER Metal3 ;
        RECT 0.000 4.420 0.400 4.820 ;
    END
  END W1BEG[1]
  PIN W1BEG[2]
    DIRECTION OUTPUT ;
    USE SIGNAL ;
    ANTENNADIFFAREA 0.708600 ;
    PORT
      LAYER Metal3 ;
        RECT 0.000 6.100 0.400 6.500 ;
    END
  END W1BEG[2]
  PIN W1BEG[3]
    DIRECTION OUTPUT ;
    USE SIGNAL ;
    ANTENNADIFFAREA 0.708600 ;
    PORT
      LAYER Metal3 ;
        RECT 0.000 7.780 0.400 8.180 ;
    END
  END W1BEG[3]
  PIN W1END[0]
    DIRECTION INPUT ;
    USE SIGNAL ;
    ANTENNAGATEAREA 0.696800 ;
    ANTENNADIFFAREA 18.138599 ;
    PORT
      LAYER Metal3 ;
        RECT 219.440 2.740 219.840 3.140 ;
    END
  END W1END[0]
  PIN W1END[1]
    DIRECTION INPUT ;
    USE SIGNAL ;
    ANTENNAGATEAREA 1.775800 ;
    PORT
      LAYER Metal3 ;
        RECT 219.440 4.420 219.840 4.820 ;
    END
  END W1END[1]
  PIN W1END[2]
    DIRECTION INPUT ;
    USE SIGNAL ;
    ANTENNAGATEAREA 2.334800 ;
    PORT
      LAYER Metal3 ;
        RECT 219.440 6.100 219.840 6.500 ;
    END
  END W1END[2]
  PIN W1END[3]
    DIRECTION INPUT ;
    USE SIGNAL ;
    ANTENNAGATEAREA 2.411500 ;
    PORT
      LAYER Metal3 ;
        RECT 219.440 7.780 219.840 8.180 ;
    END
  END W1END[3]
  PIN W2BEG[0]
    DIRECTION OUTPUT ;
    USE SIGNAL ;
    ANTENNADIFFAREA 0.708600 ;
    PORT
      LAYER Metal3 ;
        RECT 0.000 9.460 0.400 9.860 ;
    END
  END W2BEG[0]
  PIN W2BEG[1]
    DIRECTION OUTPUT ;
    USE SIGNAL ;
    ANTENNADIFFAREA 0.708600 ;
    PORT
      LAYER Metal3 ;
        RECT 0.000 11.140 0.400 11.540 ;
    END
  END W2BEG[1]
  PIN W2BEG[2]
    DIRECTION OUTPUT ;
    USE SIGNAL ;
    ANTENNADIFFAREA 0.708600 ;
    PORT
      LAYER Metal3 ;
        RECT 0.000 12.820 0.400 13.220 ;
    END
  END W2BEG[2]
  PIN W2BEG[3]
    DIRECTION OUTPUT ;
    USE SIGNAL ;
    ANTENNADIFFAREA 0.708600 ;
    PORT
      LAYER Metal3 ;
        RECT 0.000 14.500 0.400 14.900 ;
    END
  END W2BEG[3]
  PIN W2BEG[4]
    DIRECTION OUTPUT ;
    USE SIGNAL ;
    ANTENNADIFFAREA 0.708600 ;
    PORT
      LAYER Metal3 ;
        RECT 0.000 16.180 0.400 16.580 ;
    END
  END W2BEG[4]
  PIN W2BEG[5]
    DIRECTION OUTPUT ;
    USE SIGNAL ;
    ANTENNADIFFAREA 0.708600 ;
    PORT
      LAYER Metal3 ;
        RECT 0.000 17.860 0.400 18.260 ;
    END
  END W2BEG[5]
  PIN W2BEG[6]
    DIRECTION OUTPUT ;
    USE SIGNAL ;
    ANTENNADIFFAREA 0.708600 ;
    PORT
      LAYER Metal3 ;
        RECT 0.000 19.540 0.400 19.940 ;
    END
  END W2BEG[6]
  PIN W2BEG[7]
    DIRECTION OUTPUT ;
    USE SIGNAL ;
    ANTENNADIFFAREA 0.708600 ;
    PORT
      LAYER Metal3 ;
        RECT 0.000 21.220 0.400 21.620 ;
    END
  END W2BEG[7]
  PIN W2BEGb[0]
    DIRECTION OUTPUT ;
    USE SIGNAL ;
    ANTENNADIFFAREA 0.708600 ;
    PORT
      LAYER Metal3 ;
        RECT 0.000 22.900 0.400 23.300 ;
    END
  END W2BEGb[0]
  PIN W2BEGb[1]
    DIRECTION OUTPUT ;
    USE SIGNAL ;
    ANTENNADIFFAREA 0.708600 ;
    PORT
      LAYER Metal3 ;
        RECT 0.000 24.580 0.400 24.980 ;
    END
  END W2BEGb[1]
  PIN W2BEGb[2]
    DIRECTION OUTPUT ;
    USE SIGNAL ;
    ANTENNADIFFAREA 0.708600 ;
    PORT
      LAYER Metal3 ;
        RECT 0.000 26.260 0.400 26.660 ;
    END
  END W2BEGb[2]
  PIN W2BEGb[3]
    DIRECTION OUTPUT ;
    USE SIGNAL ;
    ANTENNADIFFAREA 0.708600 ;
    PORT
      LAYER Metal3 ;
        RECT 0.000 27.940 0.400 28.340 ;
    END
  END W2BEGb[3]
  PIN W2BEGb[4]
    DIRECTION OUTPUT ;
    USE SIGNAL ;
    ANTENNADIFFAREA 0.708600 ;
    PORT
      LAYER Metal3 ;
        RECT 0.000 29.620 0.400 30.020 ;
    END
  END W2BEGb[4]
  PIN W2BEGb[5]
    DIRECTION OUTPUT ;
    USE SIGNAL ;
    ANTENNADIFFAREA 0.708600 ;
    PORT
      LAYER Metal3 ;
        RECT 0.000 31.300 0.400 31.700 ;
    END
  END W2BEGb[5]
  PIN W2BEGb[6]
    DIRECTION OUTPUT ;
    USE SIGNAL ;
    ANTENNADIFFAREA 0.708600 ;
    PORT
      LAYER Metal3 ;
        RECT 0.000 32.980 0.400 33.380 ;
    END
  END W2BEGb[6]
  PIN W2BEGb[7]
    DIRECTION OUTPUT ;
    USE SIGNAL ;
    ANTENNADIFFAREA 0.708600 ;
    PORT
      LAYER Metal3 ;
        RECT 0.000 34.660 0.400 35.060 ;
    END
  END W2BEGb[7]
  PIN W2END[0]
    DIRECTION INPUT ;
    USE SIGNAL ;
    ANTENNAGATEAREA 0.455000 ;
    PORT
      LAYER Metal3 ;
        RECT 219.440 22.900 219.840 23.300 ;
    END
  END W2END[0]
  PIN W2END[1]
    DIRECTION INPUT ;
    USE SIGNAL ;
    ANTENNAGATEAREA 1.359800 ;
    PORT
      LAYER Metal3 ;
        RECT 219.440 24.580 219.840 24.980 ;
    END
  END W2END[1]
  PIN W2END[2]
    DIRECTION INPUT ;
    USE SIGNAL ;
    ANTENNAGATEAREA 1.443800 ;
    PORT
      LAYER Metal3 ;
        RECT 219.440 26.260 219.840 26.660 ;
    END
  END W2END[2]
  PIN W2END[3]
    DIRECTION INPUT ;
    USE SIGNAL ;
    ANTENNAGATEAREA 1.406900 ;
    PORT
      LAYER Metal3 ;
        RECT 219.440 27.940 219.840 28.340 ;
    END
  END W2END[3]
  PIN W2END[4]
    DIRECTION INPUT ;
    USE SIGNAL ;
    ANTENNAGATEAREA 1.547000 ;
    PORT
      LAYER Metal3 ;
        RECT 219.440 29.620 219.840 30.020 ;
    END
  END W2END[4]
  PIN W2END[5]
    DIRECTION INPUT ;
    USE SIGNAL ;
    ANTENNAGATEAREA 0.426400 ;
    PORT
      LAYER Metal3 ;
        RECT 219.440 31.300 219.840 31.700 ;
    END
  END W2END[5]
  PIN W2END[6]
    DIRECTION INPUT ;
    USE SIGNAL ;
    ANTENNAGATEAREA 0.426400 ;
    PORT
      LAYER Metal3 ;
        RECT 219.440 32.980 219.840 33.380 ;
    END
  END W2END[6]
  PIN W2END[7]
    DIRECTION INPUT ;
    USE SIGNAL ;
    ANTENNAGATEAREA 0.668200 ;
    PORT
      LAYER Metal3 ;
        RECT 219.440 34.660 219.840 35.060 ;
    END
  END W2END[7]
  PIN W2MID[0]
    DIRECTION INPUT ;
    USE SIGNAL ;
    ANTENNAGATEAREA 0.787800 ;
    ANTENNADIFFAREA 16.123199 ;
    PORT
      LAYER Metal3 ;
        RECT 219.440 9.460 219.840 9.860 ;
    END
  END W2MID[0]
  PIN W2MID[1]
    DIRECTION INPUT ;
    USE SIGNAL ;
    ANTENNAGATEAREA 1.033500 ;
    PORT
      LAYER Metal3 ;
        RECT 219.440 11.140 219.840 11.540 ;
    END
  END W2MID[1]
  PIN W2MID[2]
    DIRECTION INPUT ;
    USE SIGNAL ;
    ANTENNAGATEAREA 0.848900 ;
    ANTENNADIFFAREA 32.246399 ;
    PORT
      LAYER Metal3 ;
        RECT 219.440 12.820 219.840 13.220 ;
    END
  END W2MID[2]
  PIN W2MID[3]
    DIRECTION INPUT ;
    USE SIGNAL ;
    ANTENNAGATEAREA 1.033500 ;
    PORT
      LAYER Metal3 ;
        RECT 219.440 14.500 219.840 14.900 ;
    END
  END W2MID[3]
  PIN W2MID[4]
    DIRECTION INPUT ;
    USE SIGNAL ;
    ANTENNAGATEAREA 0.820300 ;
    ANTENNADIFFAREA 32.246399 ;
    PORT
      LAYER Metal3 ;
        RECT 219.440 16.180 219.840 16.580 ;
    END
  END W2MID[4]
  PIN W2MID[5]
    DIRECTION INPUT ;
    USE SIGNAL ;
    ANTENNAGATEAREA 1.033500 ;
    PORT
      LAYER Metal3 ;
        RECT 219.440 17.860 219.840 18.260 ;
    END
  END W2MID[5]
  PIN W2MID[6]
    DIRECTION INPUT ;
    USE SIGNAL ;
    ANTENNAGATEAREA 0.820300 ;
    ANTENNADIFFAREA 32.246399 ;
    PORT
      LAYER Metal3 ;
        RECT 219.440 19.540 219.840 19.940 ;
    END
  END W2MID[6]
  PIN W2MID[7]
    DIRECTION INPUT ;
    USE SIGNAL ;
    ANTENNAGATEAREA 1.033500 ;
    PORT
      LAYER Metal3 ;
        RECT 219.440 21.220 219.840 21.620 ;
    END
  END W2MID[7]
  PIN W6BEG[0]
    DIRECTION OUTPUT ;
    USE SIGNAL ;
    ANTENNADIFFAREA 0.708600 ;
    PORT
      LAYER Metal3 ;
        RECT 0.000 63.220 0.400 63.620 ;
    END
  END W6BEG[0]
  PIN W6BEG[10]
    DIRECTION OUTPUT ;
    USE SIGNAL ;
    ANTENNADIFFAREA 0.708600 ;
    PORT
      LAYER Metal3 ;
        RECT 0.000 80.020 0.400 80.420 ;
    END
  END W6BEG[10]
  PIN W6BEG[11]
    DIRECTION OUTPUT ;
    USE SIGNAL ;
    ANTENNADIFFAREA 0.708600 ;
    PORT
      LAYER Metal3 ;
        RECT 0.000 81.700 0.400 82.100 ;
    END
  END W6BEG[11]
  PIN W6BEG[1]
    DIRECTION OUTPUT ;
    USE SIGNAL ;
    ANTENNADIFFAREA 0.708600 ;
    PORT
      LAYER Metal3 ;
        RECT 0.000 64.900 0.400 65.300 ;
    END
  END W6BEG[1]
  PIN W6BEG[2]
    DIRECTION OUTPUT ;
    USE SIGNAL ;
    ANTENNADIFFAREA 0.708600 ;
    PORT
      LAYER Metal3 ;
        RECT 0.000 66.580 0.400 66.980 ;
    END
  END W6BEG[2]
  PIN W6BEG[3]
    DIRECTION OUTPUT ;
    USE SIGNAL ;
    ANTENNADIFFAREA 0.708600 ;
    PORT
      LAYER Metal3 ;
        RECT 0.000 68.260 0.400 68.660 ;
    END
  END W6BEG[3]
  PIN W6BEG[4]
    DIRECTION OUTPUT ;
    USE SIGNAL ;
    ANTENNADIFFAREA 0.708600 ;
    PORT
      LAYER Metal3 ;
        RECT 0.000 69.940 0.400 70.340 ;
    END
  END W6BEG[4]
  PIN W6BEG[5]
    DIRECTION OUTPUT ;
    USE SIGNAL ;
    ANTENNADIFFAREA 0.708600 ;
    PORT
      LAYER Metal3 ;
        RECT 0.000 71.620 0.400 72.020 ;
    END
  END W6BEG[5]
  PIN W6BEG[6]
    DIRECTION OUTPUT ;
    USE SIGNAL ;
    ANTENNADIFFAREA 0.708600 ;
    PORT
      LAYER Metal3 ;
        RECT 0.000 73.300 0.400 73.700 ;
    END
  END W6BEG[6]
  PIN W6BEG[7]
    DIRECTION OUTPUT ;
    USE SIGNAL ;
    ANTENNADIFFAREA 0.708600 ;
    PORT
      LAYER Metal3 ;
        RECT 0.000 74.980 0.400 75.380 ;
    END
  END W6BEG[7]
  PIN W6BEG[8]
    DIRECTION OUTPUT ;
    USE SIGNAL ;
    ANTENNADIFFAREA 0.708600 ;
    PORT
      LAYER Metal3 ;
        RECT 0.000 76.660 0.400 77.060 ;
    END
  END W6BEG[8]
  PIN W6BEG[9]
    DIRECTION OUTPUT ;
    USE SIGNAL ;
    ANTENNADIFFAREA 0.708600 ;
    PORT
      LAYER Metal3 ;
        RECT 0.000 78.340 0.400 78.740 ;
    END
  END W6BEG[9]
  PIN W6END[0]
    DIRECTION INPUT ;
    USE SIGNAL ;
    ANTENNAGATEAREA 1.526200 ;
    PORT
      LAYER Metal3 ;
        RECT 219.440 63.220 219.840 63.620 ;
    END
  END W6END[0]
  PIN W6END[10]
    DIRECTION INPUT ;
    USE SIGNAL ;
    ANTENNAGATEAREA 0.180700 ;
    PORT
      LAYER Metal3 ;
        RECT 219.440 80.020 219.840 80.420 ;
    END
  END W6END[10]
  PIN W6END[11]
    DIRECTION INPUT ;
    USE SIGNAL ;
    ANTENNAGATEAREA 0.180700 ;
    ANTENNADIFFAREA 2.015400 ;
    PORT
      LAYER Metal3 ;
        RECT 219.440 81.700 219.840 82.100 ;
    END
  END W6END[11]
  PIN W6END[1]
    DIRECTION INPUT ;
    USE SIGNAL ;
    ANTENNAGATEAREA 2.206100 ;
    PORT
      LAYER Metal3 ;
        RECT 219.440 64.900 219.840 65.300 ;
    END
  END W6END[1]
  PIN W6END[2]
    DIRECTION INPUT ;
    USE SIGNAL ;
    ANTENNAGATEAREA 0.180700 ;
    PORT
      LAYER Metal3 ;
        RECT 219.440 66.580 219.840 66.980 ;
    END
  END W6END[2]
  PIN W6END[3]
    DIRECTION INPUT ;
    USE SIGNAL ;
    ANTENNAGATEAREA 0.180700 ;
    PORT
      LAYER Metal3 ;
        RECT 219.440 68.260 219.840 68.660 ;
    END
  END W6END[3]
  PIN W6END[4]
    DIRECTION INPUT ;
    USE SIGNAL ;
    ANTENNAGATEAREA 0.180700 ;
    ANTENNADIFFAREA 2.015400 ;
    PORT
      LAYER Metal3 ;
        RECT 219.440 69.940 219.840 70.340 ;
    END
  END W6END[4]
  PIN W6END[5]
    DIRECTION INPUT ;
    USE SIGNAL ;
    ANTENNAGATEAREA 0.180700 ;
    PORT
      LAYER Metal3 ;
        RECT 219.440 71.620 219.840 72.020 ;
    END
  END W6END[5]
  PIN W6END[6]
    DIRECTION INPUT ;
    USE SIGNAL ;
    ANTENNAGATEAREA 0.180700 ;
    PORT
      LAYER Metal3 ;
        RECT 219.440 73.300 219.840 73.700 ;
    END
  END W6END[6]
  PIN W6END[7]
    DIRECTION INPUT ;
    USE SIGNAL ;
    ANTENNAGATEAREA 0.180700 ;
    ANTENNADIFFAREA 2.015400 ;
    PORT
      LAYER Metal3 ;
        RECT 219.440 74.980 219.840 75.380 ;
    END
  END W6END[7]
  PIN W6END[8]
    DIRECTION INPUT ;
    USE SIGNAL ;
    ANTENNAGATEAREA 0.180700 ;
    ANTENNADIFFAREA 2.015400 ;
    PORT
      LAYER Metal3 ;
        RECT 219.440 76.660 219.840 77.060 ;
    END
  END W6END[8]
  PIN W6END[9]
    DIRECTION INPUT ;
    USE SIGNAL ;
    ANTENNAGATEAREA 0.180700 ;
    PORT
      LAYER Metal3 ;
        RECT 219.440 78.340 219.840 78.740 ;
    END
  END W6END[9]
  PIN WW4BEG[0]
    DIRECTION OUTPUT ;
    USE SIGNAL ;
    ANTENNADIFFAREA 0.708600 ;
    PORT
      LAYER Metal3 ;
        RECT 0.000 36.340 0.400 36.740 ;
    END
  END WW4BEG[0]
  PIN WW4BEG[10]
    DIRECTION OUTPUT ;
    USE SIGNAL ;
    ANTENNADIFFAREA 0.708600 ;
    PORT
      LAYER Metal3 ;
        RECT 0.000 53.140 0.400 53.540 ;
    END
  END WW4BEG[10]
  PIN WW4BEG[11]
    DIRECTION OUTPUT ;
    USE SIGNAL ;
    ANTENNADIFFAREA 0.708600 ;
    PORT
      LAYER Metal3 ;
        RECT 0.000 54.820 0.400 55.220 ;
    END
  END WW4BEG[11]
  PIN WW4BEG[12]
    DIRECTION OUTPUT ;
    USE SIGNAL ;
    ANTENNADIFFAREA 0.708600 ;
    PORT
      LAYER Metal3 ;
        RECT 0.000 56.500 0.400 56.900 ;
    END
  END WW4BEG[12]
  PIN WW4BEG[13]
    DIRECTION OUTPUT ;
    USE SIGNAL ;
    ANTENNADIFFAREA 0.708600 ;
    PORT
      LAYER Metal3 ;
        RECT 0.000 58.180 0.400 58.580 ;
    END
  END WW4BEG[13]
  PIN WW4BEG[14]
    DIRECTION OUTPUT ;
    USE SIGNAL ;
    ANTENNADIFFAREA 0.708600 ;
    PORT
      LAYER Metal3 ;
        RECT 0.000 59.860 0.400 60.260 ;
    END
  END WW4BEG[14]
  PIN WW4BEG[15]
    DIRECTION OUTPUT ;
    USE SIGNAL ;
    ANTENNADIFFAREA 0.708600 ;
    PORT
      LAYER Metal3 ;
        RECT 0.000 61.540 0.400 61.940 ;
    END
  END WW4BEG[15]
  PIN WW4BEG[1]
    DIRECTION OUTPUT ;
    USE SIGNAL ;
    ANTENNADIFFAREA 0.708600 ;
    PORT
      LAYER Metal3 ;
        RECT 0.000 38.020 0.400 38.420 ;
    END
  END WW4BEG[1]
  PIN WW4BEG[2]
    DIRECTION OUTPUT ;
    USE SIGNAL ;
    ANTENNADIFFAREA 0.708600 ;
    PORT
      LAYER Metal3 ;
        RECT 0.000 39.700 0.400 40.100 ;
    END
  END WW4BEG[2]
  PIN WW4BEG[3]
    DIRECTION OUTPUT ;
    USE SIGNAL ;
    ANTENNADIFFAREA 0.708600 ;
    PORT
      LAYER Metal3 ;
        RECT 0.000 41.380 0.400 41.780 ;
    END
  END WW4BEG[3]
  PIN WW4BEG[4]
    DIRECTION OUTPUT ;
    USE SIGNAL ;
    ANTENNADIFFAREA 0.708600 ;
    PORT
      LAYER Metal3 ;
        RECT 0.000 43.060 0.400 43.460 ;
    END
  END WW4BEG[4]
  PIN WW4BEG[5]
    DIRECTION OUTPUT ;
    USE SIGNAL ;
    ANTENNADIFFAREA 0.708600 ;
    PORT
      LAYER Metal3 ;
        RECT 0.000 44.740 0.400 45.140 ;
    END
  END WW4BEG[5]
  PIN WW4BEG[6]
    DIRECTION OUTPUT ;
    USE SIGNAL ;
    ANTENNADIFFAREA 0.708600 ;
    PORT
      LAYER Metal3 ;
        RECT 0.000 46.420 0.400 46.820 ;
    END
  END WW4BEG[6]
  PIN WW4BEG[7]
    DIRECTION OUTPUT ;
    USE SIGNAL ;
    ANTENNADIFFAREA 0.708600 ;
    PORT
      LAYER Metal3 ;
        RECT 0.000 48.100 0.400 48.500 ;
    END
  END WW4BEG[7]
  PIN WW4BEG[8]
    DIRECTION OUTPUT ;
    USE SIGNAL ;
    ANTENNADIFFAREA 0.708600 ;
    PORT
      LAYER Metal3 ;
        RECT 0.000 49.780 0.400 50.180 ;
    END
  END WW4BEG[8]
  PIN WW4BEG[9]
    DIRECTION OUTPUT ;
    USE SIGNAL ;
    ANTENNADIFFAREA 0.708600 ;
    PORT
      LAYER Metal3 ;
        RECT 0.000 51.460 0.400 51.860 ;
    END
  END WW4BEG[9]
  PIN WW4END[0]
    DIRECTION INPUT ;
    USE SIGNAL ;
    ANTENNAGATEAREA 0.652600 ;
    ANTENNADIFFAREA 18.138599 ;
    PORT
      LAYER Metal3 ;
        RECT 219.440 36.340 219.840 36.740 ;
    END
  END WW4END[0]
  PIN WW4END[10]
    DIRECTION INPUT ;
    USE SIGNAL ;
    ANTENNAGATEAREA 0.180700 ;
    PORT
      LAYER Metal3 ;
        RECT 219.440 53.140 219.840 53.540 ;
    END
  END WW4END[10]
  PIN WW4END[11]
    DIRECTION INPUT ;
    USE SIGNAL ;
    ANTENNAGATEAREA 0.180700 ;
    PORT
      LAYER Metal3 ;
        RECT 219.440 54.820 219.840 55.220 ;
    END
  END WW4END[11]
  PIN WW4END[12]
    DIRECTION INPUT ;
    USE SIGNAL ;
    ANTENNAGATEAREA 0.180700 ;
    PORT
      LAYER Metal3 ;
        RECT 219.440 56.500 219.840 56.900 ;
    END
  END WW4END[12]
  PIN WW4END[13]
    DIRECTION INPUT ;
    USE SIGNAL ;
    ANTENNAGATEAREA 0.180700 ;
    PORT
      LAYER Metal3 ;
        RECT 219.440 58.180 219.840 58.580 ;
    END
  END WW4END[13]
  PIN WW4END[14]
    DIRECTION INPUT ;
    USE SIGNAL ;
    ANTENNAGATEAREA 0.180700 ;
    PORT
      LAYER Metal3 ;
        RECT 219.440 59.860 219.840 60.260 ;
    END
  END WW4END[14]
  PIN WW4END[15]
    DIRECTION INPUT ;
    USE SIGNAL ;
    ANTENNAGATEAREA 0.180700 ;
    PORT
      LAYER Metal3 ;
        RECT 219.440 61.540 219.840 61.940 ;
    END
  END WW4END[15]
  PIN WW4END[1]
    DIRECTION INPUT ;
    USE SIGNAL ;
    ANTENNAGATEAREA 0.455000 ;
    PORT
      LAYER Metal3 ;
        RECT 219.440 38.020 219.840 38.420 ;
    END
  END WW4END[1]
  PIN WW4END[2]
    DIRECTION INPUT ;
    USE SIGNAL ;
    ANTENNAGATEAREA 0.800800 ;
    ANTENNADIFFAREA 32.246399 ;
    PORT
      LAYER Metal3 ;
        RECT 219.440 39.700 219.840 40.100 ;
    END
  END WW4END[2]
  PIN WW4END[3]
    DIRECTION INPUT ;
    USE SIGNAL ;
    ANTENNAGATEAREA 0.652600 ;
    PORT
      LAYER Metal3 ;
        RECT 219.440 41.380 219.840 41.780 ;
    END
  END WW4END[3]
  PIN WW4END[4]
    DIRECTION INPUT ;
    USE SIGNAL ;
    ANTENNAGATEAREA 0.180700 ;
    PORT
      LAYER Metal3 ;
        RECT 219.440 43.060 219.840 43.460 ;
    END
  END WW4END[4]
  PIN WW4END[5]
    DIRECTION INPUT ;
    USE SIGNAL ;
    ANTENNAGATEAREA 0.180700 ;
    PORT
      LAYER Metal3 ;
        RECT 219.440 44.740 219.840 45.140 ;
    END
  END WW4END[5]
  PIN WW4END[6]
    DIRECTION INPUT ;
    USE SIGNAL ;
    ANTENNAGATEAREA 0.180700 ;
    PORT
      LAYER Metal3 ;
        RECT 219.440 46.420 219.840 46.820 ;
    END
  END WW4END[6]
  PIN WW4END[7]
    DIRECTION INPUT ;
    USE SIGNAL ;
    ANTENNAGATEAREA 0.180700 ;
    ANTENNADIFFAREA 2.015400 ;
    PORT
      LAYER Metal3 ;
        RECT 219.440 48.100 219.840 48.500 ;
    END
  END WW4END[7]
  PIN WW4END[8]
    DIRECTION INPUT ;
    USE SIGNAL ;
    ANTENNAGATEAREA 0.180700 ;
    PORT
      LAYER Metal3 ;
        RECT 219.440 49.780 219.840 50.180 ;
    END
  END WW4END[8]
  PIN WW4END[9]
    DIRECTION INPUT ;
    USE SIGNAL ;
    ANTENNAGATEAREA 0.180700 ;
    PORT
      LAYER Metal3 ;
        RECT 219.440 51.460 219.840 51.860 ;
    END
  END WW4END[9]
  OBS
      LAYER GatPoly ;
        RECT 2.880 3.630 216.960 215.610 ;
      LAYER Metal1 ;
        RECT 2.880 3.560 216.960 215.680 ;
      LAYER Metal2 ;
        RECT 0.375 218.630 49.030 218.965 ;
        RECT 49.850 218.630 49.990 218.965 ;
        RECT 50.810 218.630 50.950 218.965 ;
        RECT 51.770 218.630 51.910 218.965 ;
        RECT 52.730 218.630 52.870 218.965 ;
        RECT 53.690 218.630 53.830 218.965 ;
        RECT 54.650 218.630 54.790 218.965 ;
        RECT 55.610 218.630 55.750 218.965 ;
        RECT 56.570 218.630 56.710 218.965 ;
        RECT 57.530 218.630 57.670 218.965 ;
        RECT 58.490 218.630 58.630 218.965 ;
        RECT 59.450 218.630 59.590 218.965 ;
        RECT 60.410 218.630 60.550 218.965 ;
        RECT 61.370 218.630 61.510 218.965 ;
        RECT 62.330 218.630 62.470 218.965 ;
        RECT 63.290 218.630 63.430 218.965 ;
        RECT 64.250 218.630 64.390 218.965 ;
        RECT 65.210 218.630 65.350 218.965 ;
        RECT 66.170 218.630 66.310 218.965 ;
        RECT 67.130 218.630 67.270 218.965 ;
        RECT 68.090 218.630 68.230 218.965 ;
        RECT 69.050 218.630 69.190 218.965 ;
        RECT 70.010 218.630 70.150 218.965 ;
        RECT 70.970 218.630 71.110 218.965 ;
        RECT 71.930 218.630 72.070 218.965 ;
        RECT 72.890 218.630 73.030 218.965 ;
        RECT 73.850 218.630 73.990 218.965 ;
        RECT 74.810 218.630 74.950 218.965 ;
        RECT 75.770 218.630 75.910 218.965 ;
        RECT 76.730 218.630 76.870 218.965 ;
        RECT 77.690 218.630 77.830 218.965 ;
        RECT 78.650 218.630 78.790 218.965 ;
        RECT 79.610 218.630 79.750 218.965 ;
        RECT 80.570 218.630 80.710 218.965 ;
        RECT 81.530 218.630 81.670 218.965 ;
        RECT 82.490 218.630 82.630 218.965 ;
        RECT 83.450 218.630 83.590 218.965 ;
        RECT 84.410 218.630 84.550 218.965 ;
        RECT 85.370 218.630 85.510 218.965 ;
        RECT 86.330 218.630 86.470 218.965 ;
        RECT 87.290 218.630 87.430 218.965 ;
        RECT 88.250 218.630 88.390 218.965 ;
        RECT 89.210 218.630 89.350 218.965 ;
        RECT 90.170 218.630 90.310 218.965 ;
        RECT 91.130 218.630 91.270 218.965 ;
        RECT 92.090 218.630 92.230 218.965 ;
        RECT 93.050 218.630 93.190 218.965 ;
        RECT 94.010 218.630 94.150 218.965 ;
        RECT 94.970 218.630 95.110 218.965 ;
        RECT 95.930 218.630 96.070 218.965 ;
        RECT 96.890 218.630 97.030 218.965 ;
        RECT 97.850 218.630 97.990 218.965 ;
        RECT 98.810 218.630 98.950 218.965 ;
        RECT 99.770 218.630 99.910 218.965 ;
        RECT 100.730 218.630 100.870 218.965 ;
        RECT 101.690 218.630 101.830 218.965 ;
        RECT 102.650 218.630 102.790 218.965 ;
        RECT 103.610 218.630 103.750 218.965 ;
        RECT 104.570 218.630 104.710 218.965 ;
        RECT 105.530 218.630 105.670 218.965 ;
        RECT 106.490 218.630 106.630 218.965 ;
        RECT 107.450 218.630 107.590 218.965 ;
        RECT 108.410 218.630 108.550 218.965 ;
        RECT 109.370 218.630 109.510 218.965 ;
        RECT 110.330 218.630 110.470 218.965 ;
        RECT 111.290 218.630 111.430 218.965 ;
        RECT 112.250 218.630 112.390 218.965 ;
        RECT 113.210 218.630 113.350 218.965 ;
        RECT 114.170 218.630 114.310 218.965 ;
        RECT 115.130 218.630 115.270 218.965 ;
        RECT 116.090 218.630 116.230 218.965 ;
        RECT 117.050 218.630 117.190 218.965 ;
        RECT 118.010 218.630 118.150 218.965 ;
        RECT 118.970 218.630 119.110 218.965 ;
        RECT 119.930 218.630 120.070 218.965 ;
        RECT 120.890 218.630 121.030 218.965 ;
        RECT 121.850 218.630 121.990 218.965 ;
        RECT 122.810 218.630 122.950 218.965 ;
        RECT 123.770 218.630 123.910 218.965 ;
        RECT 124.730 218.630 124.870 218.965 ;
        RECT 125.690 218.630 125.830 218.965 ;
        RECT 126.650 218.630 126.790 218.965 ;
        RECT 127.610 218.630 127.750 218.965 ;
        RECT 128.570 218.630 128.710 218.965 ;
        RECT 129.530 218.630 129.670 218.965 ;
        RECT 130.490 218.630 130.630 218.965 ;
        RECT 131.450 218.630 131.590 218.965 ;
        RECT 132.410 218.630 132.550 218.965 ;
        RECT 133.370 218.630 133.510 218.965 ;
        RECT 134.330 218.630 134.470 218.965 ;
        RECT 135.290 218.630 135.430 218.965 ;
        RECT 136.250 218.630 136.390 218.965 ;
        RECT 137.210 218.630 137.350 218.965 ;
        RECT 138.170 218.630 138.310 218.965 ;
        RECT 139.130 218.630 139.270 218.965 ;
        RECT 140.090 218.630 140.230 218.965 ;
        RECT 141.050 218.630 141.190 218.965 ;
        RECT 142.010 218.630 142.150 218.965 ;
        RECT 142.970 218.630 143.110 218.965 ;
        RECT 143.930 218.630 144.070 218.965 ;
        RECT 144.890 218.630 145.030 218.965 ;
        RECT 145.850 218.630 145.990 218.965 ;
        RECT 146.810 218.630 146.950 218.965 ;
        RECT 147.770 218.630 147.910 218.965 ;
        RECT 148.730 218.630 148.870 218.965 ;
        RECT 149.690 218.630 149.830 218.965 ;
        RECT 150.650 218.630 150.790 218.965 ;
        RECT 151.610 218.630 151.750 218.965 ;
        RECT 152.570 218.630 152.710 218.965 ;
        RECT 153.530 218.630 153.670 218.965 ;
        RECT 154.490 218.630 154.630 218.965 ;
        RECT 155.450 218.630 155.590 218.965 ;
        RECT 156.410 218.630 156.550 218.965 ;
        RECT 157.370 218.630 157.510 218.965 ;
        RECT 158.330 218.630 158.470 218.965 ;
        RECT 159.290 218.630 159.430 218.965 ;
        RECT 160.250 218.630 160.390 218.965 ;
        RECT 161.210 218.630 161.350 218.965 ;
        RECT 162.170 218.630 162.310 218.965 ;
        RECT 163.130 218.630 163.270 218.965 ;
        RECT 164.090 218.630 164.230 218.965 ;
        RECT 165.050 218.630 165.190 218.965 ;
        RECT 166.010 218.630 166.150 218.965 ;
        RECT 166.970 218.630 167.110 218.965 ;
        RECT 167.930 218.630 168.070 218.965 ;
        RECT 168.890 218.630 169.030 218.965 ;
        RECT 169.850 218.630 219.465 218.965 ;
        RECT 0.375 0.610 219.465 218.630 ;
        RECT 0.375 0.320 49.030 0.610 ;
        RECT 49.850 0.320 49.990 0.610 ;
        RECT 50.810 0.320 50.950 0.610 ;
        RECT 51.770 0.320 51.910 0.610 ;
        RECT 52.730 0.320 52.870 0.610 ;
        RECT 53.690 0.320 53.830 0.610 ;
        RECT 54.650 0.320 54.790 0.610 ;
        RECT 55.610 0.320 55.750 0.610 ;
        RECT 56.570 0.320 56.710 0.610 ;
        RECT 57.530 0.320 57.670 0.610 ;
        RECT 58.490 0.320 58.630 0.610 ;
        RECT 59.450 0.320 59.590 0.610 ;
        RECT 60.410 0.320 60.550 0.610 ;
        RECT 61.370 0.320 61.510 0.610 ;
        RECT 62.330 0.320 62.470 0.610 ;
        RECT 63.290 0.320 63.430 0.610 ;
        RECT 64.250 0.320 64.390 0.610 ;
        RECT 65.210 0.320 65.350 0.610 ;
        RECT 66.170 0.320 66.310 0.610 ;
        RECT 67.130 0.320 67.270 0.610 ;
        RECT 68.090 0.320 68.230 0.610 ;
        RECT 69.050 0.320 69.190 0.610 ;
        RECT 70.010 0.320 70.150 0.610 ;
        RECT 70.970 0.320 71.110 0.610 ;
        RECT 71.930 0.320 72.070 0.610 ;
        RECT 72.890 0.320 73.030 0.610 ;
        RECT 73.850 0.320 73.990 0.610 ;
        RECT 74.810 0.320 74.950 0.610 ;
        RECT 75.770 0.320 75.910 0.610 ;
        RECT 76.730 0.320 76.870 0.610 ;
        RECT 77.690 0.320 77.830 0.610 ;
        RECT 78.650 0.320 78.790 0.610 ;
        RECT 79.610 0.320 79.750 0.610 ;
        RECT 80.570 0.320 80.710 0.610 ;
        RECT 81.530 0.320 81.670 0.610 ;
        RECT 82.490 0.320 82.630 0.610 ;
        RECT 83.450 0.320 83.590 0.610 ;
        RECT 84.410 0.320 84.550 0.610 ;
        RECT 85.370 0.320 85.510 0.610 ;
        RECT 86.330 0.320 86.470 0.610 ;
        RECT 87.290 0.320 87.430 0.610 ;
        RECT 88.250 0.320 88.390 0.610 ;
        RECT 89.210 0.320 89.350 0.610 ;
        RECT 90.170 0.320 90.310 0.610 ;
        RECT 91.130 0.320 91.270 0.610 ;
        RECT 92.090 0.320 92.230 0.610 ;
        RECT 93.050 0.320 93.190 0.610 ;
        RECT 94.010 0.320 94.150 0.610 ;
        RECT 94.970 0.320 95.110 0.610 ;
        RECT 95.930 0.320 96.070 0.610 ;
        RECT 96.890 0.320 97.030 0.610 ;
        RECT 97.850 0.320 97.990 0.610 ;
        RECT 98.810 0.320 98.950 0.610 ;
        RECT 99.770 0.320 99.910 0.610 ;
        RECT 100.730 0.320 100.870 0.610 ;
        RECT 101.690 0.320 101.830 0.610 ;
        RECT 102.650 0.320 102.790 0.610 ;
        RECT 103.610 0.320 103.750 0.610 ;
        RECT 104.570 0.320 104.710 0.610 ;
        RECT 105.530 0.320 105.670 0.610 ;
        RECT 106.490 0.320 106.630 0.610 ;
        RECT 107.450 0.320 107.590 0.610 ;
        RECT 108.410 0.320 108.550 0.610 ;
        RECT 109.370 0.320 109.510 0.610 ;
        RECT 110.330 0.320 110.470 0.610 ;
        RECT 111.290 0.320 111.430 0.610 ;
        RECT 112.250 0.320 112.390 0.610 ;
        RECT 113.210 0.320 113.350 0.610 ;
        RECT 114.170 0.320 114.310 0.610 ;
        RECT 115.130 0.320 115.270 0.610 ;
        RECT 116.090 0.320 116.230 0.610 ;
        RECT 117.050 0.320 117.190 0.610 ;
        RECT 118.010 0.320 118.150 0.610 ;
        RECT 118.970 0.320 119.110 0.610 ;
        RECT 119.930 0.320 120.070 0.610 ;
        RECT 120.890 0.320 121.030 0.610 ;
        RECT 121.850 0.320 121.990 0.610 ;
        RECT 122.810 0.320 122.950 0.610 ;
        RECT 123.770 0.320 123.910 0.610 ;
        RECT 124.730 0.320 124.870 0.610 ;
        RECT 125.690 0.320 125.830 0.610 ;
        RECT 126.650 0.320 126.790 0.610 ;
        RECT 127.610 0.320 127.750 0.610 ;
        RECT 128.570 0.320 128.710 0.610 ;
        RECT 129.530 0.320 129.670 0.610 ;
        RECT 130.490 0.320 130.630 0.610 ;
        RECT 131.450 0.320 131.590 0.610 ;
        RECT 132.410 0.320 132.550 0.610 ;
        RECT 133.370 0.320 133.510 0.610 ;
        RECT 134.330 0.320 134.470 0.610 ;
        RECT 135.290 0.320 135.430 0.610 ;
        RECT 136.250 0.320 136.390 0.610 ;
        RECT 137.210 0.320 137.350 0.610 ;
        RECT 138.170 0.320 138.310 0.610 ;
        RECT 139.130 0.320 139.270 0.610 ;
        RECT 140.090 0.320 140.230 0.610 ;
        RECT 141.050 0.320 141.190 0.610 ;
        RECT 142.010 0.320 142.150 0.610 ;
        RECT 142.970 0.320 143.110 0.610 ;
        RECT 143.930 0.320 144.070 0.610 ;
        RECT 144.890 0.320 145.030 0.610 ;
        RECT 145.850 0.320 145.990 0.610 ;
        RECT 146.810 0.320 146.950 0.610 ;
        RECT 147.770 0.320 147.910 0.610 ;
        RECT 148.730 0.320 148.870 0.610 ;
        RECT 149.690 0.320 149.830 0.610 ;
        RECT 150.650 0.320 150.790 0.610 ;
        RECT 151.610 0.320 151.750 0.610 ;
        RECT 152.570 0.320 152.710 0.610 ;
        RECT 153.530 0.320 153.670 0.610 ;
        RECT 154.490 0.320 154.630 0.610 ;
        RECT 155.450 0.320 155.590 0.610 ;
        RECT 156.410 0.320 156.550 0.610 ;
        RECT 157.370 0.320 157.510 0.610 ;
        RECT 158.330 0.320 158.470 0.610 ;
        RECT 159.290 0.320 159.430 0.610 ;
        RECT 160.250 0.320 160.390 0.610 ;
        RECT 161.210 0.320 161.350 0.610 ;
        RECT 162.170 0.320 162.310 0.610 ;
        RECT 163.130 0.320 163.270 0.610 ;
        RECT 164.090 0.320 164.230 0.610 ;
        RECT 165.050 0.320 165.190 0.610 ;
        RECT 166.010 0.320 166.150 0.610 ;
        RECT 166.970 0.320 167.110 0.610 ;
        RECT 167.930 0.320 168.070 0.610 ;
        RECT 168.890 0.320 169.030 0.610 ;
        RECT 169.850 0.320 219.465 0.610 ;
      LAYER Metal3 ;
        RECT 0.335 216.710 219.505 218.925 ;
        RECT 0.610 215.890 219.230 216.710 ;
        RECT 0.335 215.030 219.505 215.890 ;
        RECT 0.610 214.210 219.230 215.030 ;
        RECT 0.335 213.350 219.505 214.210 ;
        RECT 0.610 212.530 219.230 213.350 ;
        RECT 0.335 211.670 219.505 212.530 ;
        RECT 0.610 210.850 219.230 211.670 ;
        RECT 0.335 209.990 219.505 210.850 ;
        RECT 0.610 209.170 219.230 209.990 ;
        RECT 0.335 208.310 219.505 209.170 ;
        RECT 0.610 207.490 219.230 208.310 ;
        RECT 0.335 206.630 219.505 207.490 ;
        RECT 0.610 205.810 219.230 206.630 ;
        RECT 0.335 204.950 219.505 205.810 ;
        RECT 0.610 204.130 219.230 204.950 ;
        RECT 0.335 203.270 219.505 204.130 ;
        RECT 0.610 202.450 219.230 203.270 ;
        RECT 0.335 201.590 219.505 202.450 ;
        RECT 0.610 200.770 219.230 201.590 ;
        RECT 0.335 199.910 219.505 200.770 ;
        RECT 0.610 199.090 219.230 199.910 ;
        RECT 0.335 198.230 219.505 199.090 ;
        RECT 0.610 197.410 219.230 198.230 ;
        RECT 0.335 196.550 219.505 197.410 ;
        RECT 0.610 195.730 219.230 196.550 ;
        RECT 0.335 194.870 219.505 195.730 ;
        RECT 0.610 194.050 219.230 194.870 ;
        RECT 0.335 193.190 219.505 194.050 ;
        RECT 0.610 192.370 219.230 193.190 ;
        RECT 0.335 191.510 219.505 192.370 ;
        RECT 0.610 190.690 219.230 191.510 ;
        RECT 0.335 189.830 219.505 190.690 ;
        RECT 0.610 189.010 219.230 189.830 ;
        RECT 0.335 188.150 219.505 189.010 ;
        RECT 0.610 187.330 219.230 188.150 ;
        RECT 0.335 186.470 219.505 187.330 ;
        RECT 0.610 185.650 219.230 186.470 ;
        RECT 0.335 184.790 219.505 185.650 ;
        RECT 0.610 183.970 219.230 184.790 ;
        RECT 0.335 183.110 219.505 183.970 ;
        RECT 0.610 182.290 219.230 183.110 ;
        RECT 0.335 181.430 219.505 182.290 ;
        RECT 0.610 180.610 219.230 181.430 ;
        RECT 0.335 179.750 219.505 180.610 ;
        RECT 0.610 178.930 219.230 179.750 ;
        RECT 0.335 178.070 219.505 178.930 ;
        RECT 0.610 177.250 219.230 178.070 ;
        RECT 0.335 176.390 219.505 177.250 ;
        RECT 0.610 175.570 219.230 176.390 ;
        RECT 0.335 174.710 219.505 175.570 ;
        RECT 0.610 173.890 219.230 174.710 ;
        RECT 0.335 173.030 219.505 173.890 ;
        RECT 0.610 172.210 219.230 173.030 ;
        RECT 0.335 171.350 219.505 172.210 ;
        RECT 0.610 170.530 219.230 171.350 ;
        RECT 0.335 169.670 219.505 170.530 ;
        RECT 0.610 168.850 219.230 169.670 ;
        RECT 0.335 167.990 219.505 168.850 ;
        RECT 0.610 167.170 219.230 167.990 ;
        RECT 0.335 166.310 219.505 167.170 ;
        RECT 0.610 165.490 219.230 166.310 ;
        RECT 0.335 164.630 219.505 165.490 ;
        RECT 0.610 163.810 219.230 164.630 ;
        RECT 0.335 162.950 219.505 163.810 ;
        RECT 0.610 162.130 219.230 162.950 ;
        RECT 0.335 161.270 219.505 162.130 ;
        RECT 0.610 160.450 219.230 161.270 ;
        RECT 0.335 159.590 219.505 160.450 ;
        RECT 0.610 158.770 219.230 159.590 ;
        RECT 0.335 157.910 219.505 158.770 ;
        RECT 0.610 157.090 219.230 157.910 ;
        RECT 0.335 156.230 219.505 157.090 ;
        RECT 0.610 155.410 219.230 156.230 ;
        RECT 0.335 154.550 219.505 155.410 ;
        RECT 0.610 153.730 219.230 154.550 ;
        RECT 0.335 152.870 219.505 153.730 ;
        RECT 0.610 152.050 219.230 152.870 ;
        RECT 0.335 151.190 219.505 152.050 ;
        RECT 0.610 150.370 219.230 151.190 ;
        RECT 0.335 149.510 219.505 150.370 ;
        RECT 0.610 148.690 219.230 149.510 ;
        RECT 0.335 147.830 219.505 148.690 ;
        RECT 0.610 147.010 219.230 147.830 ;
        RECT 0.335 146.150 219.505 147.010 ;
        RECT 0.610 145.330 219.230 146.150 ;
        RECT 0.335 144.470 219.505 145.330 ;
        RECT 0.610 143.650 219.230 144.470 ;
        RECT 0.335 142.790 219.505 143.650 ;
        RECT 0.610 141.970 219.230 142.790 ;
        RECT 0.335 141.110 219.505 141.970 ;
        RECT 0.610 140.290 219.230 141.110 ;
        RECT 0.335 139.430 219.505 140.290 ;
        RECT 0.610 138.610 219.230 139.430 ;
        RECT 0.335 137.750 219.505 138.610 ;
        RECT 0.610 136.930 219.230 137.750 ;
        RECT 0.335 136.070 219.505 136.930 ;
        RECT 0.610 135.250 219.230 136.070 ;
        RECT 0.335 134.390 219.505 135.250 ;
        RECT 0.610 133.570 219.230 134.390 ;
        RECT 0.335 132.710 219.505 133.570 ;
        RECT 0.610 131.890 219.230 132.710 ;
        RECT 0.335 131.030 219.505 131.890 ;
        RECT 0.610 130.210 219.230 131.030 ;
        RECT 0.335 129.350 219.505 130.210 ;
        RECT 0.610 128.530 219.230 129.350 ;
        RECT 0.335 127.670 219.505 128.530 ;
        RECT 0.610 126.850 219.230 127.670 ;
        RECT 0.335 125.990 219.505 126.850 ;
        RECT 0.610 125.170 219.230 125.990 ;
        RECT 0.335 124.310 219.505 125.170 ;
        RECT 0.610 123.490 219.230 124.310 ;
        RECT 0.335 122.630 219.505 123.490 ;
        RECT 0.610 121.810 219.230 122.630 ;
        RECT 0.335 120.950 219.505 121.810 ;
        RECT 0.610 120.130 219.230 120.950 ;
        RECT 0.335 119.270 219.505 120.130 ;
        RECT 0.610 118.450 219.230 119.270 ;
        RECT 0.335 117.590 219.505 118.450 ;
        RECT 0.610 116.770 219.230 117.590 ;
        RECT 0.335 115.910 219.505 116.770 ;
        RECT 0.610 115.090 219.230 115.910 ;
        RECT 0.335 114.230 219.505 115.090 ;
        RECT 0.610 113.410 219.230 114.230 ;
        RECT 0.335 112.550 219.505 113.410 ;
        RECT 0.610 111.730 219.230 112.550 ;
        RECT 0.335 110.870 219.505 111.730 ;
        RECT 0.610 110.050 219.230 110.870 ;
        RECT 0.335 109.190 219.505 110.050 ;
        RECT 0.610 108.370 219.230 109.190 ;
        RECT 0.335 107.510 219.505 108.370 ;
        RECT 0.610 106.690 219.230 107.510 ;
        RECT 0.335 105.830 219.505 106.690 ;
        RECT 0.610 105.010 219.230 105.830 ;
        RECT 0.335 104.150 219.505 105.010 ;
        RECT 0.610 103.330 219.230 104.150 ;
        RECT 0.335 102.470 219.505 103.330 ;
        RECT 0.610 101.650 219.230 102.470 ;
        RECT 0.335 100.790 219.505 101.650 ;
        RECT 0.610 99.970 219.230 100.790 ;
        RECT 0.335 99.110 219.505 99.970 ;
        RECT 0.610 98.290 219.230 99.110 ;
        RECT 0.335 97.430 219.505 98.290 ;
        RECT 0.610 96.610 219.230 97.430 ;
        RECT 0.335 95.750 219.505 96.610 ;
        RECT 0.610 94.930 219.230 95.750 ;
        RECT 0.335 94.070 219.505 94.930 ;
        RECT 0.610 93.250 219.230 94.070 ;
        RECT 0.335 92.390 219.505 93.250 ;
        RECT 0.610 91.570 219.230 92.390 ;
        RECT 0.335 90.710 219.505 91.570 ;
        RECT 0.610 89.890 219.230 90.710 ;
        RECT 0.335 89.030 219.505 89.890 ;
        RECT 0.610 88.210 219.230 89.030 ;
        RECT 0.335 87.350 219.505 88.210 ;
        RECT 0.610 86.530 219.230 87.350 ;
        RECT 0.335 85.670 219.505 86.530 ;
        RECT 0.610 84.850 219.230 85.670 ;
        RECT 0.335 83.990 219.505 84.850 ;
        RECT 0.610 83.170 219.230 83.990 ;
        RECT 0.335 82.310 219.505 83.170 ;
        RECT 0.610 81.490 219.230 82.310 ;
        RECT 0.335 80.630 219.505 81.490 ;
        RECT 0.610 79.810 219.230 80.630 ;
        RECT 0.335 78.950 219.505 79.810 ;
        RECT 0.610 78.130 219.230 78.950 ;
        RECT 0.335 77.270 219.505 78.130 ;
        RECT 0.610 76.450 219.230 77.270 ;
        RECT 0.335 75.590 219.505 76.450 ;
        RECT 0.610 74.770 219.230 75.590 ;
        RECT 0.335 73.910 219.505 74.770 ;
        RECT 0.610 73.090 219.230 73.910 ;
        RECT 0.335 72.230 219.505 73.090 ;
        RECT 0.610 71.410 219.230 72.230 ;
        RECT 0.335 70.550 219.505 71.410 ;
        RECT 0.610 69.730 219.230 70.550 ;
        RECT 0.335 68.870 219.505 69.730 ;
        RECT 0.610 68.050 219.230 68.870 ;
        RECT 0.335 67.190 219.505 68.050 ;
        RECT 0.610 66.370 219.230 67.190 ;
        RECT 0.335 65.510 219.505 66.370 ;
        RECT 0.610 64.690 219.230 65.510 ;
        RECT 0.335 63.830 219.505 64.690 ;
        RECT 0.610 63.010 219.230 63.830 ;
        RECT 0.335 62.150 219.505 63.010 ;
        RECT 0.610 61.330 219.230 62.150 ;
        RECT 0.335 60.470 219.505 61.330 ;
        RECT 0.610 59.650 219.230 60.470 ;
        RECT 0.335 58.790 219.505 59.650 ;
        RECT 0.610 57.970 219.230 58.790 ;
        RECT 0.335 57.110 219.505 57.970 ;
        RECT 0.610 56.290 219.230 57.110 ;
        RECT 0.335 55.430 219.505 56.290 ;
        RECT 0.610 54.610 219.230 55.430 ;
        RECT 0.335 53.750 219.505 54.610 ;
        RECT 0.610 52.930 219.230 53.750 ;
        RECT 0.335 52.070 219.505 52.930 ;
        RECT 0.610 51.250 219.230 52.070 ;
        RECT 0.335 50.390 219.505 51.250 ;
        RECT 0.610 49.570 219.230 50.390 ;
        RECT 0.335 48.710 219.505 49.570 ;
        RECT 0.610 47.890 219.230 48.710 ;
        RECT 0.335 47.030 219.505 47.890 ;
        RECT 0.610 46.210 219.230 47.030 ;
        RECT 0.335 45.350 219.505 46.210 ;
        RECT 0.610 44.530 219.230 45.350 ;
        RECT 0.335 43.670 219.505 44.530 ;
        RECT 0.610 42.850 219.230 43.670 ;
        RECT 0.335 41.990 219.505 42.850 ;
        RECT 0.610 41.170 219.230 41.990 ;
        RECT 0.335 40.310 219.505 41.170 ;
        RECT 0.610 39.490 219.230 40.310 ;
        RECT 0.335 38.630 219.505 39.490 ;
        RECT 0.610 37.810 219.230 38.630 ;
        RECT 0.335 36.950 219.505 37.810 ;
        RECT 0.610 36.130 219.230 36.950 ;
        RECT 0.335 35.270 219.505 36.130 ;
        RECT 0.610 34.450 219.230 35.270 ;
        RECT 0.335 33.590 219.505 34.450 ;
        RECT 0.610 32.770 219.230 33.590 ;
        RECT 0.335 31.910 219.505 32.770 ;
        RECT 0.610 31.090 219.230 31.910 ;
        RECT 0.335 30.230 219.505 31.090 ;
        RECT 0.610 29.410 219.230 30.230 ;
        RECT 0.335 28.550 219.505 29.410 ;
        RECT 0.610 27.730 219.230 28.550 ;
        RECT 0.335 26.870 219.505 27.730 ;
        RECT 0.610 26.050 219.230 26.870 ;
        RECT 0.335 25.190 219.505 26.050 ;
        RECT 0.610 24.370 219.230 25.190 ;
        RECT 0.335 23.510 219.505 24.370 ;
        RECT 0.610 22.690 219.230 23.510 ;
        RECT 0.335 21.830 219.505 22.690 ;
        RECT 0.610 21.010 219.230 21.830 ;
        RECT 0.335 20.150 219.505 21.010 ;
        RECT 0.610 19.330 219.230 20.150 ;
        RECT 0.335 18.470 219.505 19.330 ;
        RECT 0.610 17.650 219.230 18.470 ;
        RECT 0.335 16.790 219.505 17.650 ;
        RECT 0.610 15.970 219.230 16.790 ;
        RECT 0.335 15.110 219.505 15.970 ;
        RECT 0.610 14.290 219.230 15.110 ;
        RECT 0.335 13.430 219.505 14.290 ;
        RECT 0.610 12.610 219.230 13.430 ;
        RECT 0.335 11.750 219.505 12.610 ;
        RECT 0.610 10.930 219.230 11.750 ;
        RECT 0.335 10.070 219.505 10.930 ;
        RECT 0.610 9.250 219.230 10.070 ;
        RECT 0.335 8.390 219.505 9.250 ;
        RECT 0.610 7.570 219.230 8.390 ;
        RECT 0.335 6.710 219.505 7.570 ;
        RECT 0.610 5.890 219.230 6.710 ;
        RECT 0.335 5.030 219.505 5.890 ;
        RECT 0.610 4.210 219.230 5.030 ;
        RECT 0.335 3.350 219.505 4.210 ;
        RECT 0.610 2.530 219.230 3.350 ;
        RECT 0.335 0.315 219.505 2.530 ;
      LAYER Metal4 ;
        RECT 0.380 0.275 15.170 218.965 ;
        RECT 17.790 0.275 21.370 218.965 ;
        RECT 23.990 0.275 90.770 218.965 ;
        RECT 93.390 0.275 96.970 218.965 ;
        RECT 99.590 0.275 166.370 218.965 ;
        RECT 168.990 0.275 172.570 218.965 ;
        RECT 175.190 0.275 219.460 218.965 ;
      LAYER TopMetal1 ;
        RECT 1.580 3.100 217.780 214.500 ;
  END
END LUT4AB
END LIBRARY

